FUNCTION "FC_GRP_81_R27" : VOID
TITLE =GROUP =81-R27
{ S7_language := '9(1) Angielski (Stany Zjednoczone)  11.01.2022  09:45:15' }
VERSION : 0.1


VAR_TEMP
  CL : "UDT_CABINET";	//CABINET LOCAL
  CR : "UDT_CABINET";	//CABINET REMOTE
  RelError : BOOL ;	//ERROR RELEASE
  RelErrorCL : BOOL ;	//ERROR RELEASE FROM CABINET LOCAL
  RelErrorCR : BOOL ;	//ERROR RELEASE FROM CABINET REMOTE
  RelControl : BOOL ;	//CONTROL RELEASE
  RelControlCL : BOOL ;	//CONTROL RELEASE FROM CABINET LOCAL
  RelControlCR : BOOL ;	//CONTROL RELEASE FROM CABINET REMOTE
  ErrorConfirm : BOOL ;	//ERROR CONFIRM
  AutoOn : BOOL ;	//AUTOMATIC ON
  AutoOff : BOOL ;	//AUTOMATIC OFF
  LAMP_ON : BOOL ;
  FLOW_METER_PE : BOOL ;
  ASU_FLAPS_MT34_STOP : BOOL ;
  ASU_FLAPS_MT34_CLOSE : BOOL ;
  ASU_PREHEATING_FINISHED : BOOL ;
  OUT_TEMP_SENSOR_OK : BOOL ;	//OUTSIDE TEMPERATURE SENSOR OK
  OUT_HUM_SENSOR_OK : BOOL ;	//OUTSIDE HUMIDITY SENSOR OK
  ASU_PUMP_COOLING_STOP : BOOL ;
  H_81CLM82_HUM_SWP : REAL ;
  T_81CLT81_HEAT_SWP : REAL ;
  T_81CLT81_HEAT_SWP_MAX : REAL ;
END_VAR
BEGIN
NETWORK
TITLE =GLOBAL SIGNALS

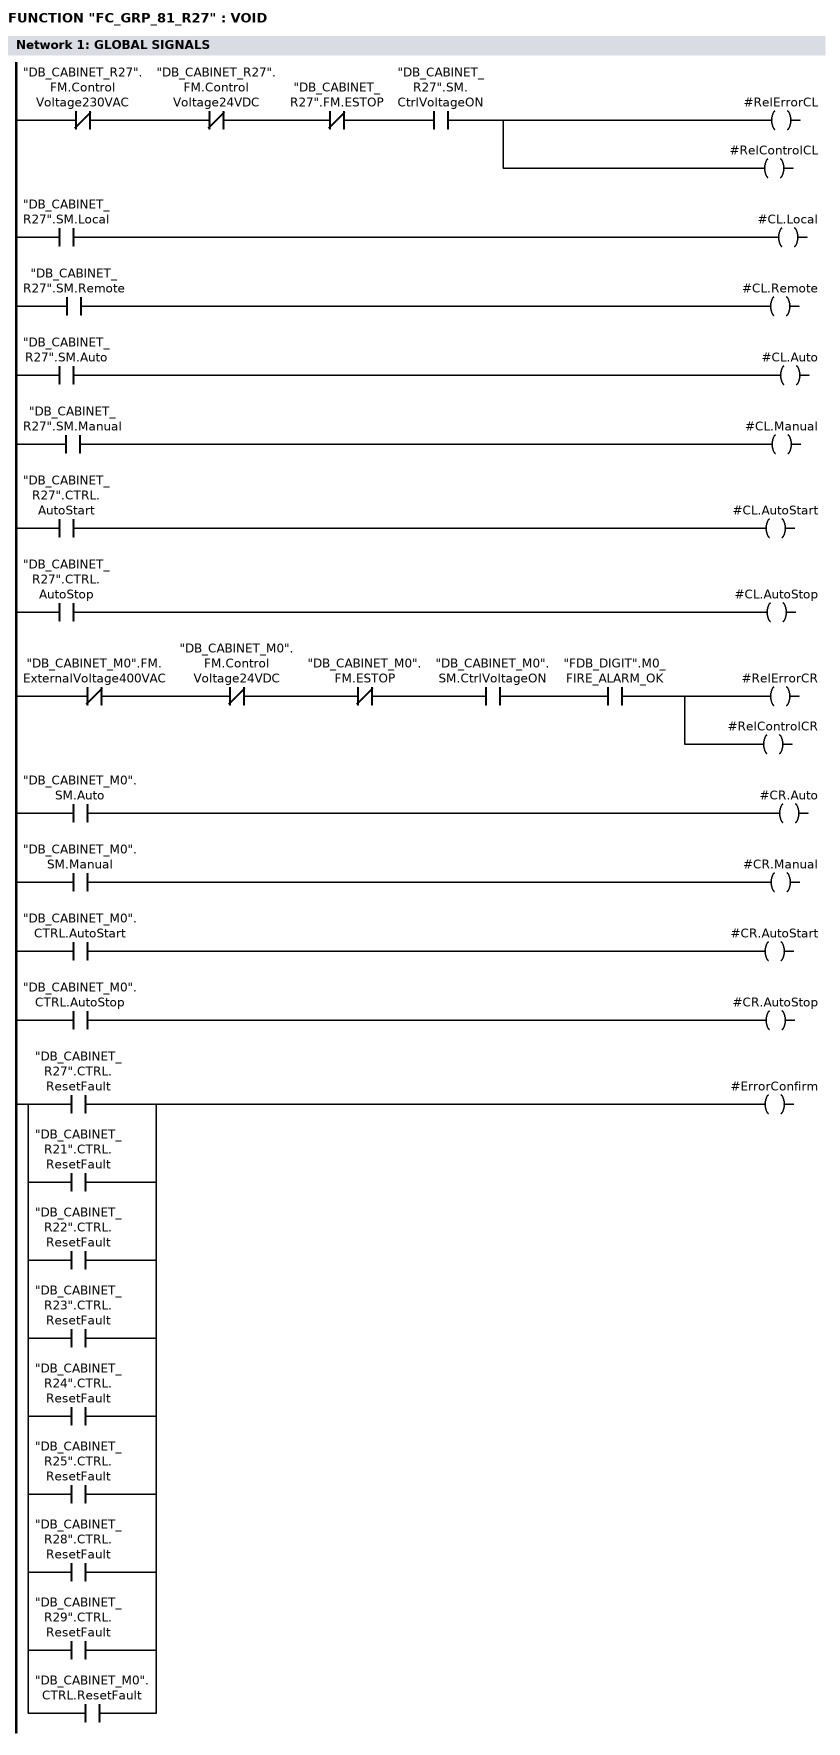
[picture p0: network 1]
// LOCAL
      UN    "DB_CABINET_R27".FM.ControlVoltage230VAC;
      UN    "DB_CABINET_R27".FM.ControlVoltage24VDC;
//      UN    "DB_CABINET_R27".FM.ControlVoltage230VAC_MS
      UN    "DB_CABINET_R27".FM.ESTOP;
      U     "DB_CABINET_R27".SM.CtrlVoltageON;
      =     #RelErrorCL;
      =     #RelControlCL;

      U     "DB_CABINET_R27".SM.Local;
      =     #CL.Local;
      U     "DB_CABINET_R27".SM.Remote;
      =     #CL.Remote;
      U     "DB_CABINET_R27".SM.Auto;
      =     #CL.Auto;
      U     "DB_CABINET_R27".SM.Manual;
      =     #CL.Manual;
      U     "DB_CABINET_R27".CTRL.AutoStart;
      =     #CL.AutoStart;
      U     "DB_CABINET_R27".CTRL.AutoStop;
      =     #CL.AutoStop;

// REMOTE
      UN    "DB_CABINET_M0".FM.ExternalVoltage400VAC;
      UN    "DB_CABINET_M0".FM.ControlVoltage24VDC;
//      UN    "DB_CABINET_M0".FM.ControlVoltage230VAC_MS
      UN    "DB_CABINET_M0".FM.ESTOP;
      U     "DB_CABINET_M0".SM.CtrlVoltageON;
      U     "FDB_DIGIT".M0_FIRE_ALARM_OK;
      =     #RelErrorCR;
      =     #RelControlCR;

      U     "DB_CABINET_M0".SM.Auto;
      =     #CR.Auto;
      U     "DB_CABINET_M0".SM.Manual;
      =     #CR.Manual;
      U     "DB_CABINET_M0".CTRL.AutoStart;
      =     #CR.AutoStart;
      U     "DB_CABINET_M0".CTRL.AutoStop;
      =     #CR.AutoStop;

      U     "DB_CABINET_R27".CTRL.ResetFault;
      O     "DB_CABINET_R21".CTRL.ResetFault;
      O     "DB_CABINET_R22".CTRL.ResetFault;
      O     "DB_CABINET_R23".CTRL.ResetFault;
      O     "DB_CABINET_R24".CTRL.ResetFault;
      O     "DB_CABINET_R25".CTRL.ResetFault;
      O     "DB_CABINET_R28".CTRL.ResetFault;
      O     "DB_CABINET_R29".CTRL.ResetFault;
      O     "DB_CABINET_M0".CTRL.ResetFault;
      =     #ErrorConfirm;

NETWORK
TITLE ==81DOO08-S1F ACCESS DOOR ERROR

      U(    ;
      U(    ;
      O     #ErrorConfirm;
      O     "R27-81DOO08+81TG1-S1:14";
      )     ;
      R     "DB_DIGIT".FM.G81_DOO08;
      U     "FDB_DIGIT".R27_81DOO08_OK;
      =     "DB_DIGIT".SM.G81_DOO08;
      U     "DB_DIGIT".SM.G81_DOO08;
      NOT   ;
      U     #RelErrorCL;
      U     #RelErrorCR;
      S     "DB_DIGIT".FM.G81_DOO08;
      U     "DB_DIGIT".FM.G81_DOO08;
      )     ;
      U     "DURATION_1";
      =     "R27-81DOO08+81TG1-H1:x1";
NETWORK
TITLE ==81FLA11/12/13/14 CONTROL/ERROR RELEASE

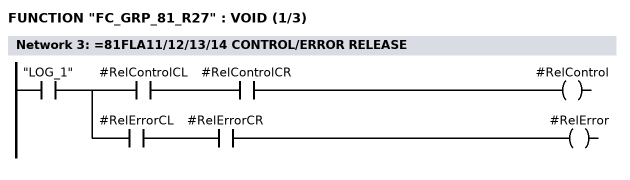
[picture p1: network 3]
      U     "LOG_1";
      =     L     20.0;
      U     L     20.0;
      U     #RelControlCL;
      U     #RelControlCR;
      =     #RelControl;
      U     L     20.0;
      U     #RelErrorCL;
      U     #RelErrorCR;
      =     #RelError;
NETWORK
TITLE ==81FLA11/12/13/14 CONTROL ALL FLAPS IN MAN. MODE / FIRE ALARM

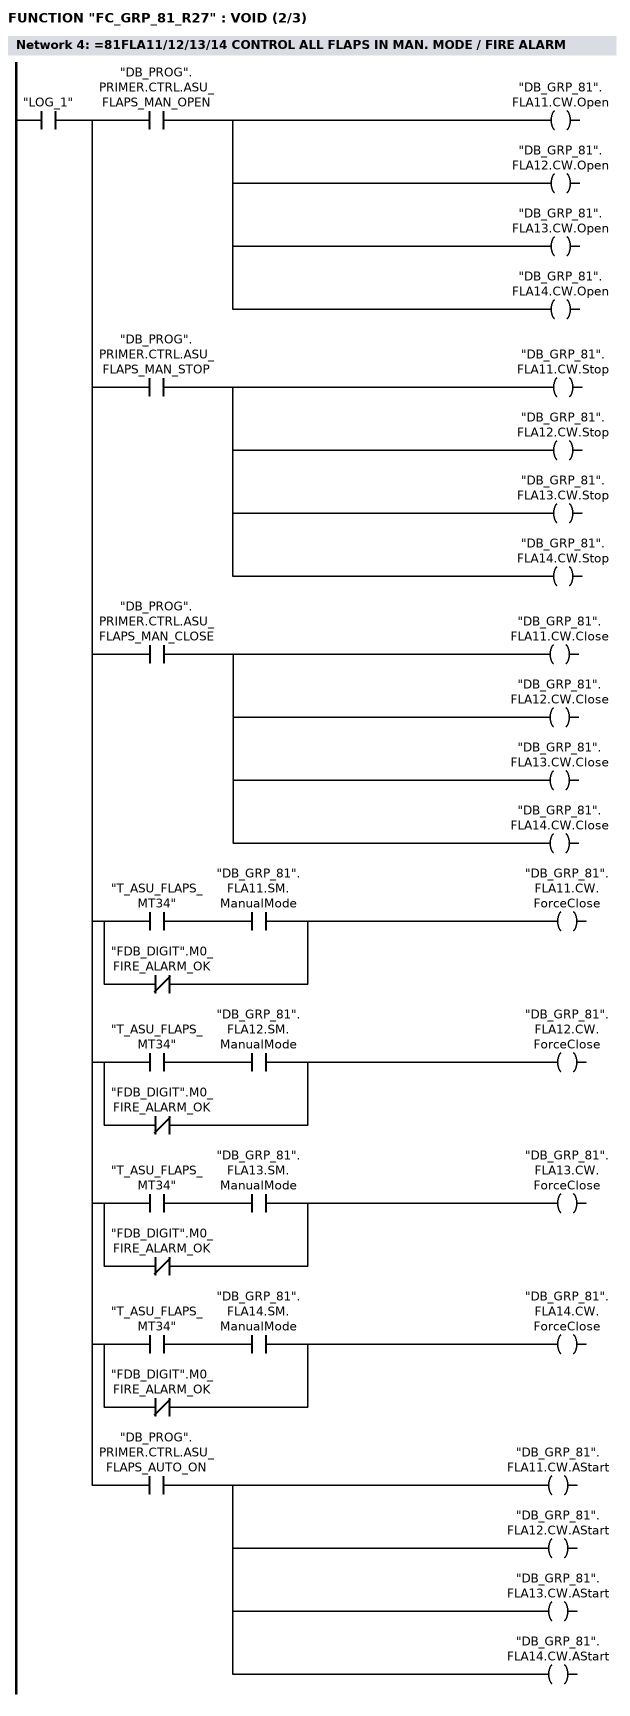
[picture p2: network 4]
      U     "LOG_1";
      =     L     20.0;
      U     L     20.0;
      U     "DB_PROG".PRIMER.CTRL.ASU_FLAPS_MAN_OPEN;
      =     "DB_GRP_81".FLA11.CW.Open;
      =     "DB_GRP_81".FLA12.CW.Open;
      =     "DB_GRP_81".FLA13.CW.Open;
      =     "DB_GRP_81".FLA14.CW.Open;
      U     L     20.0;
      U     "DB_PROG".PRIMER.CTRL.ASU_FLAPS_MAN_STOP;
      =     "DB_GRP_81".FLA11.CW.Stop;
      =     "DB_GRP_81".FLA12.CW.Stop;
      =     "DB_GRP_81".FLA13.CW.Stop;
      =     "DB_GRP_81".FLA14.CW.Stop;
      U     L     20.0;
      U     "DB_PROG".PRIMER.CTRL.ASU_FLAPS_MAN_CLOSE;
      =     "DB_GRP_81".FLA11.CW.Close;
      =     "DB_GRP_81".FLA12.CW.Close;
      =     "DB_GRP_81".FLA13.CW.Close;
      =     "DB_GRP_81".FLA14.CW.Close;
      U     L     20.0;
      U(    ;
      U     "T_ASU_FLAPS_MT34";
      U     "DB_GRP_81".FLA11.SM.ManualMode;
      ON    "FDB_DIGIT".M0_FIRE_ALARM_OK;
      )     ;
      =     "DB_GRP_81".FLA11.CW.ForceClose;
      U     L     20.0;
      U(    ;
      U     "T_ASU_FLAPS_MT34";
      U     "DB_GRP_81".FLA12.SM.ManualMode;
      ON    "FDB_DIGIT".M0_FIRE_ALARM_OK;
      )     ;
      =     "DB_GRP_81".FLA12.CW.ForceClose;
      U     L     20.0;
      U(    ;
      U     "T_ASU_FLAPS_MT34";
      U     "DB_GRP_81".FLA13.SM.ManualMode;
      ON    "FDB_DIGIT".M0_FIRE_ALARM_OK;
      )     ;
      =     "DB_GRP_81".FLA13.CW.ForceClose;
      U     L     20.0;
      U(    ;
      U     "T_ASU_FLAPS_MT34";
      U     "DB_GRP_81".FLA14.SM.ManualMode;
      ON    "FDB_DIGIT".M0_FIRE_ALARM_OK;
      )     ;
      =     "DB_GRP_81".FLA14.CW.ForceClose;
      U     L     20.0;
      U     "DB_PROG".PRIMER.CTRL.ASU_FLAPS_AUTO_ON;
      =     "DB_GRP_81".FLA11.CW.AStart;
      =     "DB_GRP_81".FLA12.CW.AStart;
      =     "DB_GRP_81".FLA13.CW.AStart;
      =     "DB_GRP_81".FLA14.CW.AStart;
NETWORK
TITLE ==81FLA11/12/13/14-M1 FROST PROTECTION TIMER

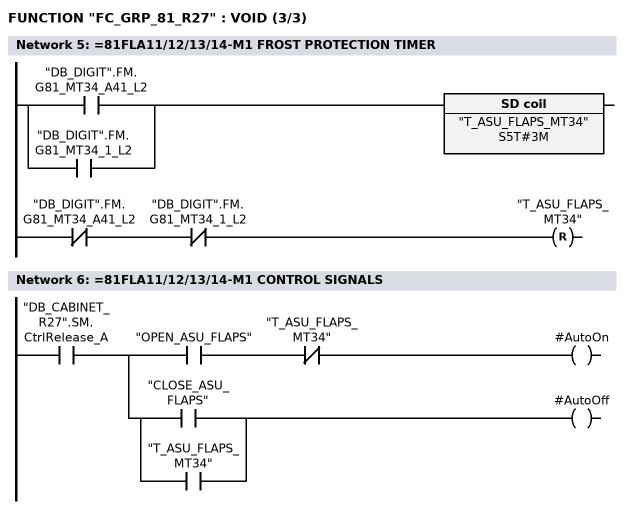
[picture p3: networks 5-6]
      U(    ;
      O     "DB_DIGIT".FM.G81_MT34_A41_L2;
      O     "DB_DIGIT".FM.G81_MT34_1_L2;
      )     ;
      L     S5T#3M;
      SE    "T_ASU_FLAPS_MT34";
      UN    "DB_DIGIT".FM.G81_MT34_A41_L2;
      UN    "DB_DIGIT".FM.G81_MT34_1_L2;
      R     "T_ASU_FLAPS_MT34";
      NOP   0;
      NOP   0;
      NOP   0;
NETWORK
TITLE ==81FLA11/12/13/14-M1 CONTROL SIGNALS

      U     "DB_CABINET_R27".SM.CtrlRelease_A;
      =     L     20.0;
      U     L     20.0;
      U     "OPEN_ASU_FLAPS";
      UN    "T_ASU_FLAPS_MT34";
      =     #AutoOn;
      U     L     20.0;
      U(    ;
      O     "CLOSE_ASU_FLAPS";
      O     "T_ASU_FLAPS_MT34";
      )     ;
      =     #AutoOff;
NETWORK
TITLE ==81FLA11-M1 CONTROL DAMPER

      U     #RelControl;
      =     L     20.0;
      BLD   103;
      U     #RelError;
      =     L     20.1;
      BLD   103;
      U     #AutoOn;
      =     L     20.2;
      BLD   103;
      U     #AutoOff;
      =     L     20.3;
      BLD   103;
      U     "LOG_1";
      =     L     20.4;
      BLD   103;
      U(    ;
      U     "R27-81FLA11+X-S1c:4";
      L     S5T#1M;
      SE    "T_81FLA11_LS_O";
      NOP   0;
      NOP   0;
      NOP   0;
      U     "T_81FLA11_LS_O";
      )     ;
      =     L     20.5;
      BLD   103;
      U(    ;
      U     "R27-81FLA11+X-S2c:4";
      L     S5T#1M;
      SE    "T_81FLA11_LS_C";
      NOP   0;
      NOP   0;
      NOP   0;
      U     "T_81FLA11_LS_C";
      )     ;
      =     L     20.6;
      BLD   103;
      U     #ErrorConfirm;
      =     L     20.7;
      BLD   103;
      CALL "FC_FLAP" (
           REL_CONTROL              := L     20.0,
           REL_ERROR                := L     20.1,
           CL                       := #CL,
           CR                       := #CR,
           AUTO_OPEN                := L     20.2,
           AUTO_CLOSE               := L     20.3,
           FUSE                     := L     20.4,
           LS_OPEN                  := L     20.5,
           LS_CLOSE                 := L     20.6,
           ERROR_CONFIRM            := L     20.7,
           MAX_RUNTIME              := 210,
           OPEN                     := "R27-81FLA11+X-M1:2",
           CLOSE                    := "R27-81FLA11+X-M1:3",
           DDB                      := "DB_GRP_81".FLA11);
      NOP   0;
NETWORK
TITLE ==81FLA12-M1 CONTROL DAMPER

      U     #RelControl;
      =     L     20.0;
      BLD   103;
      U     #RelError;
      =     L     20.1;
      BLD   103;
      U     #AutoOn;
      =     L     20.2;
      BLD   103;
      U     #AutoOff;
      =     L     20.3;
      BLD   103;
      U     "LOG_1";
      =     L     20.4;
      BLD   103;
      U(    ;
      U     "R27-81FLA12+X-S1c:4";
      L     S5T#1M;
      SE    "T_81FLA12_LS_O";
      NOP   0;
      NOP   0;
      NOP   0;
      U     "T_81FLA12_LS_O";
      )     ;
      =     L     20.5;
      BLD   103;
      U(    ;
      U     "R27-81FLA12+X-S2c:4";
      L     S5T#1M;
      SE    "T_81FLA12_LS_C";
      NOP   0;
      NOP   0;
      NOP   0;
      U     "T_81FLA12_LS_C";
      )     ;
      =     L     20.6;
      BLD   103;
      U     #ErrorConfirm;
      =     L     20.7;
      BLD   103;
      CALL "FC_FLAP" (
           REL_CONTROL              := L     20.0,
           REL_ERROR                := L     20.1,
           CL                       := #CL,
           CR                       := #CR,
           AUTO_OPEN                := L     20.2,
           AUTO_CLOSE               := L     20.3,
           FUSE                     := L     20.4,
           LS_OPEN                  := L     20.5,
           LS_CLOSE                 := L     20.6,
           ERROR_CONFIRM            := L     20.7,
           MAX_RUNTIME              := 210,
           OPEN                     := "R27-81FLA12+X-M1:2",
           CLOSE                    := "R27-81FLA12+X-M1:3",
           DDB                      := "DB_GRP_81".FLA12);
      NOP   0;
NETWORK
TITLE ==81FLA13-M1 CONTROL DAMPER

      U     #RelControl;
      =     L     20.0;
      BLD   103;
      U     #RelError;
      =     L     20.1;
      BLD   103;
      U     #AutoOn;
      =     L     20.2;
      BLD   103;
      U     #AutoOff;
      =     L     20.3;
      BLD   103;
      U     "LOG_1";
      =     L     20.4;
      BLD   103;
      U(    ;
      U     "R27-81FLA13+X-S1c:4";
      L     S5T#1M;
      SE    "T_81FLA13_LS_O";
      NOP   0;
      NOP   0;
      NOP   0;
      U     "T_81FLA13_LS_O";
      )     ;
      =     L     20.5;
      BLD   103;
      U(    ;
      U     "R27-81FLA13+X-S2c:4";
      L     S5T#1M;
      SE    "T_81FLA13_LS_C";
      NOP   0;
      NOP   0;
      NOP   0;
      U     "T_81FLA13_LS_C";
      )     ;
      =     L     20.6;
      BLD   103;
      U     #ErrorConfirm;
      =     L     20.7;
      BLD   103;
      CALL "FC_FLAP" (
           REL_CONTROL              := L     20.0,
           REL_ERROR                := L     20.1,
           CL                       := #CL,
           CR                       := #CR,
           AUTO_OPEN                := L     20.2,
           AUTO_CLOSE               := L     20.3,
           FUSE                     := L     20.4,
           LS_OPEN                  := L     20.5,
           LS_CLOSE                 := L     20.6,
           ERROR_CONFIRM            := L     20.7,
           MAX_RUNTIME              := 210,
           OPEN                     := "R27-81FLA13+X-M1:2",
           CLOSE                    := "R27-81FLA13+X-M1:3",
           DDB                      := "DB_GRP_81".FLA13);
      NOP   0;
NETWORK
TITLE ==81FLA14-M1 CONTROL DAMPER

      U     #RelControl;
      =     L     20.0;
      BLD   103;
      U     #RelError;
      =     L     20.1;
      BLD   103;
      U     #AutoOn;
      =     L     20.2;
      BLD   103;
      U     #AutoOff;
      =     L     20.3;
      BLD   103;
      U     "LOG_1";
      =     L     20.4;
      BLD   103;
      U(    ;
      U     "R27-81FLA14+X-S1c:4";
      L     S5T#1M;
      SE    "T_81FLA14_LS_O";
      NOP   0;
      NOP   0;
      NOP   0;
      U     "T_81FLA14_LS_O";
      )     ;
      =     L     20.5;
      BLD   103;
      U(    ;
      U     "R27-81FLA14+X-S2c:4";
      L     S5T#1M;
      SE    "T_81FLA14_LS_C";
      NOP   0;
      NOP   0;
      NOP   0;
      U     "T_81FLA14_LS_C";
      )     ;
      =     L     20.6;
      BLD   103;
      U     #ErrorConfirm;
      =     L     20.7;
      BLD   103;
      CALL "FC_FLAP" (
           REL_CONTROL              := L     20.0,
           REL_ERROR                := L     20.1,
           CL                       := #CL,
           CR                       := #CR,
           AUTO_OPEN                := L     20.2,
           AUTO_CLOSE               := L     20.3,
           FUSE                     := L     20.4,
           LS_OPEN                  := L     20.5,
           LS_CLOSE                 := L     20.6,
           ERROR_CONFIRM            := L     20.7,
           MAX_RUNTIME              := 210,
           OPEN                     := "R27-81FLA14+X-M1:2",
           CLOSE                    := "R27-81FLA14+X-M1:3",
           DDB                      := "DB_GRP_81".FLA14);
      NOP   0;
NETWORK
TITLE ==81FTR20-B33 FILTER PRESSURE MONITORING

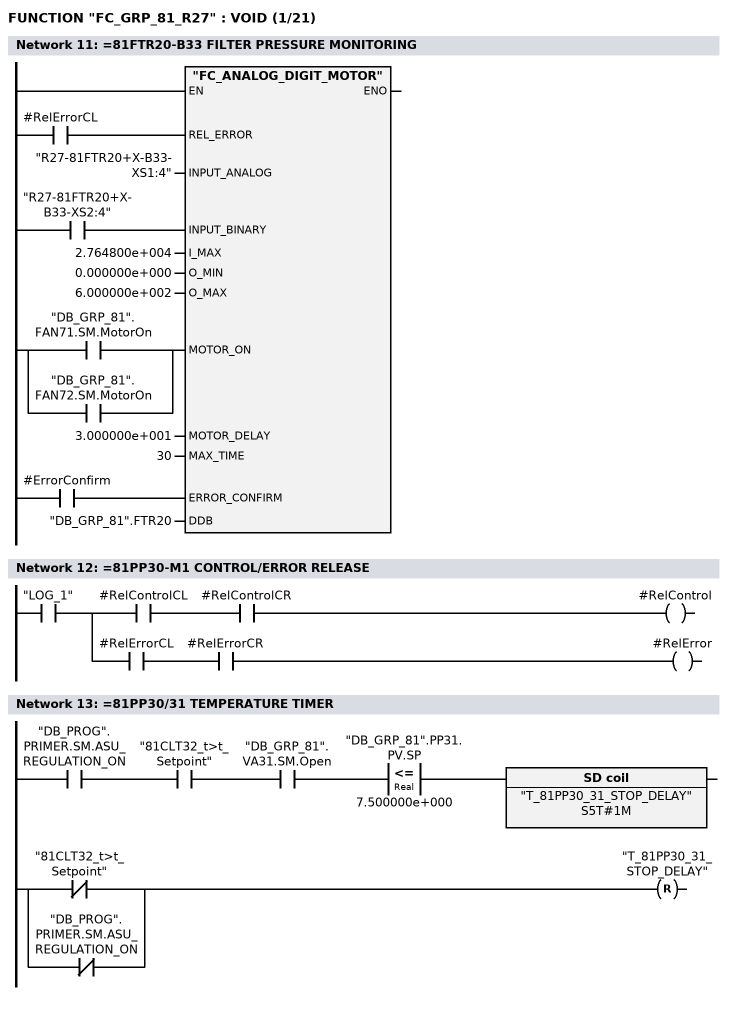
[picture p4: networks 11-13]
      U     #RelErrorCL;
      =     L     20.0;
      BLD   103;
      U     "R27-81FTR20+X-B33-XS2:4";
      =     L     20.1;
      BLD   103;
      U(    ;
      O     "DB_GRP_81".FAN71.SM.MotorOn;
      O     "DB_GRP_81".FAN72.SM.MotorOn;
      )     ;
      =     L     20.2;
      BLD   103;
      U     #ErrorConfirm;
      =     L     20.3;
      BLD   103;
      CALL "FC_ANALOG_DIGIT_MOTOR" (
           REL_ERROR                := L     20.0,
           INPUT_ANALOG             := "R27-81FTR20+X-B33-XS1:4",
           INPUT_BINARY             := L     20.1,
           I_MAX                    := 2.764800e+004,
           O_MIN                    := 0.000000e+000,
           O_MAX                    := 6.000000e+002,
           MOTOR_ON                 := L     20.2,
           MOTOR_DELAY              := 3.000000e+001,
           MAX_TIME                 := 30,
           ERROR_CONFIRM            := L     20.3,
           DDB                      := "DB_GRP_81".FTR20);
      NOP   0;
NETWORK
TITLE ==81PP30-M1 CONTROL/ERROR RELEASE

      U     "LOG_1";
      =     L     20.0;
      U     L     20.0;
      U     #RelControlCL;
      U     #RelControlCR;
      =     #RelControl;
      U     L     20.0;
      U     #RelErrorCL;
      U     #RelErrorCR;
      =     #RelError;
NETWORK
TITLE ==81PP30/31 TEMPERATURE TIMER

      U     "DB_PROG".PRIMER.SM.ASU_REGULATION_ON;
      U     "81CLT32_t>t_Setpoint";
      U     "DB_GRP_81".VA31.SM.Open;
      U(    ;
      L     "DB_GRP_81".PP31.PV.SP;
      L     7.500000e+000;
      <=R   ;
      )     ;
      L     S5T#1M;
      SE    "T_81PP30_31_STOP_DELAY";
      U(    ;
      ON    "81CLT32_t>t_Setpoint";
      ON    "DB_PROG".PRIMER.SM.ASU_REGULATION_ON;
      )     ;
      R     "T_81PP30_31_STOP_DELAY";
      NOP   0;
      NOP   0;
      NOP   0;
NETWORK
TITLE ==81PP30/31 FROST PROTECTION TIMER

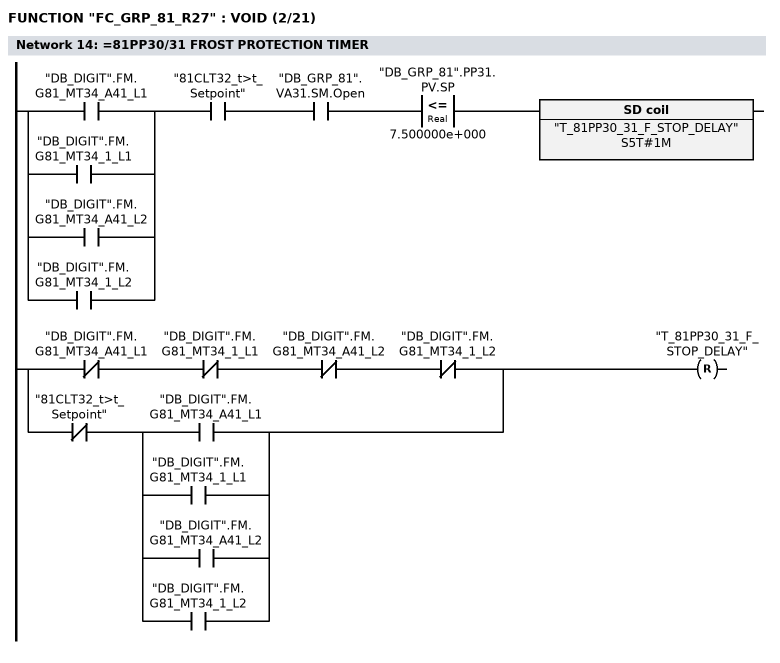
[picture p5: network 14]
      U(    ;
      O     "DB_DIGIT".FM.G81_MT34_A41_L1;
      O     "DB_DIGIT".FM.G81_MT34_1_L1;
      O     "DB_DIGIT".FM.G81_MT34_A41_L2;
      O     "DB_DIGIT".FM.G81_MT34_1_L2;
      )     ;
      U     "81CLT32_t>t_Setpoint";
      U     "DB_GRP_81".VA31.SM.Open;
      U(    ;
      L     "DB_GRP_81".PP31.PV.SP;
      L     7.500000e+000;
      <=R   ;
      )     ;
      L     S5T#1M;
      SE    "T_81PP30_31_F_STOP_DELAY";
      U(    ;
      UN    "DB_DIGIT".FM.G81_MT34_A41_L1;
      UN    "DB_DIGIT".FM.G81_MT34_1_L1;
      UN    "DB_DIGIT".FM.G81_MT34_A41_L2;
      UN    "DB_DIGIT".FM.G81_MT34_1_L2;
      O     ;
      UN    "81CLT32_t>t_Setpoint";
      U(    ;
      O     "DB_DIGIT".FM.G81_MT34_A41_L1;
      O     "DB_DIGIT".FM.G81_MT34_1_L1;
      O     "DB_DIGIT".FM.G81_MT34_A41_L2;
      O     "DB_DIGIT".FM.G81_MT34_1_L2;
      )     ;
      )     ;
      R     "T_81PP30_31_F_STOP_DELAY";
      NOP   0;
      NOP   0;
      NOP   0;
NETWORK
TITLE ==81PP30-M1 CONTROL SIGNALS

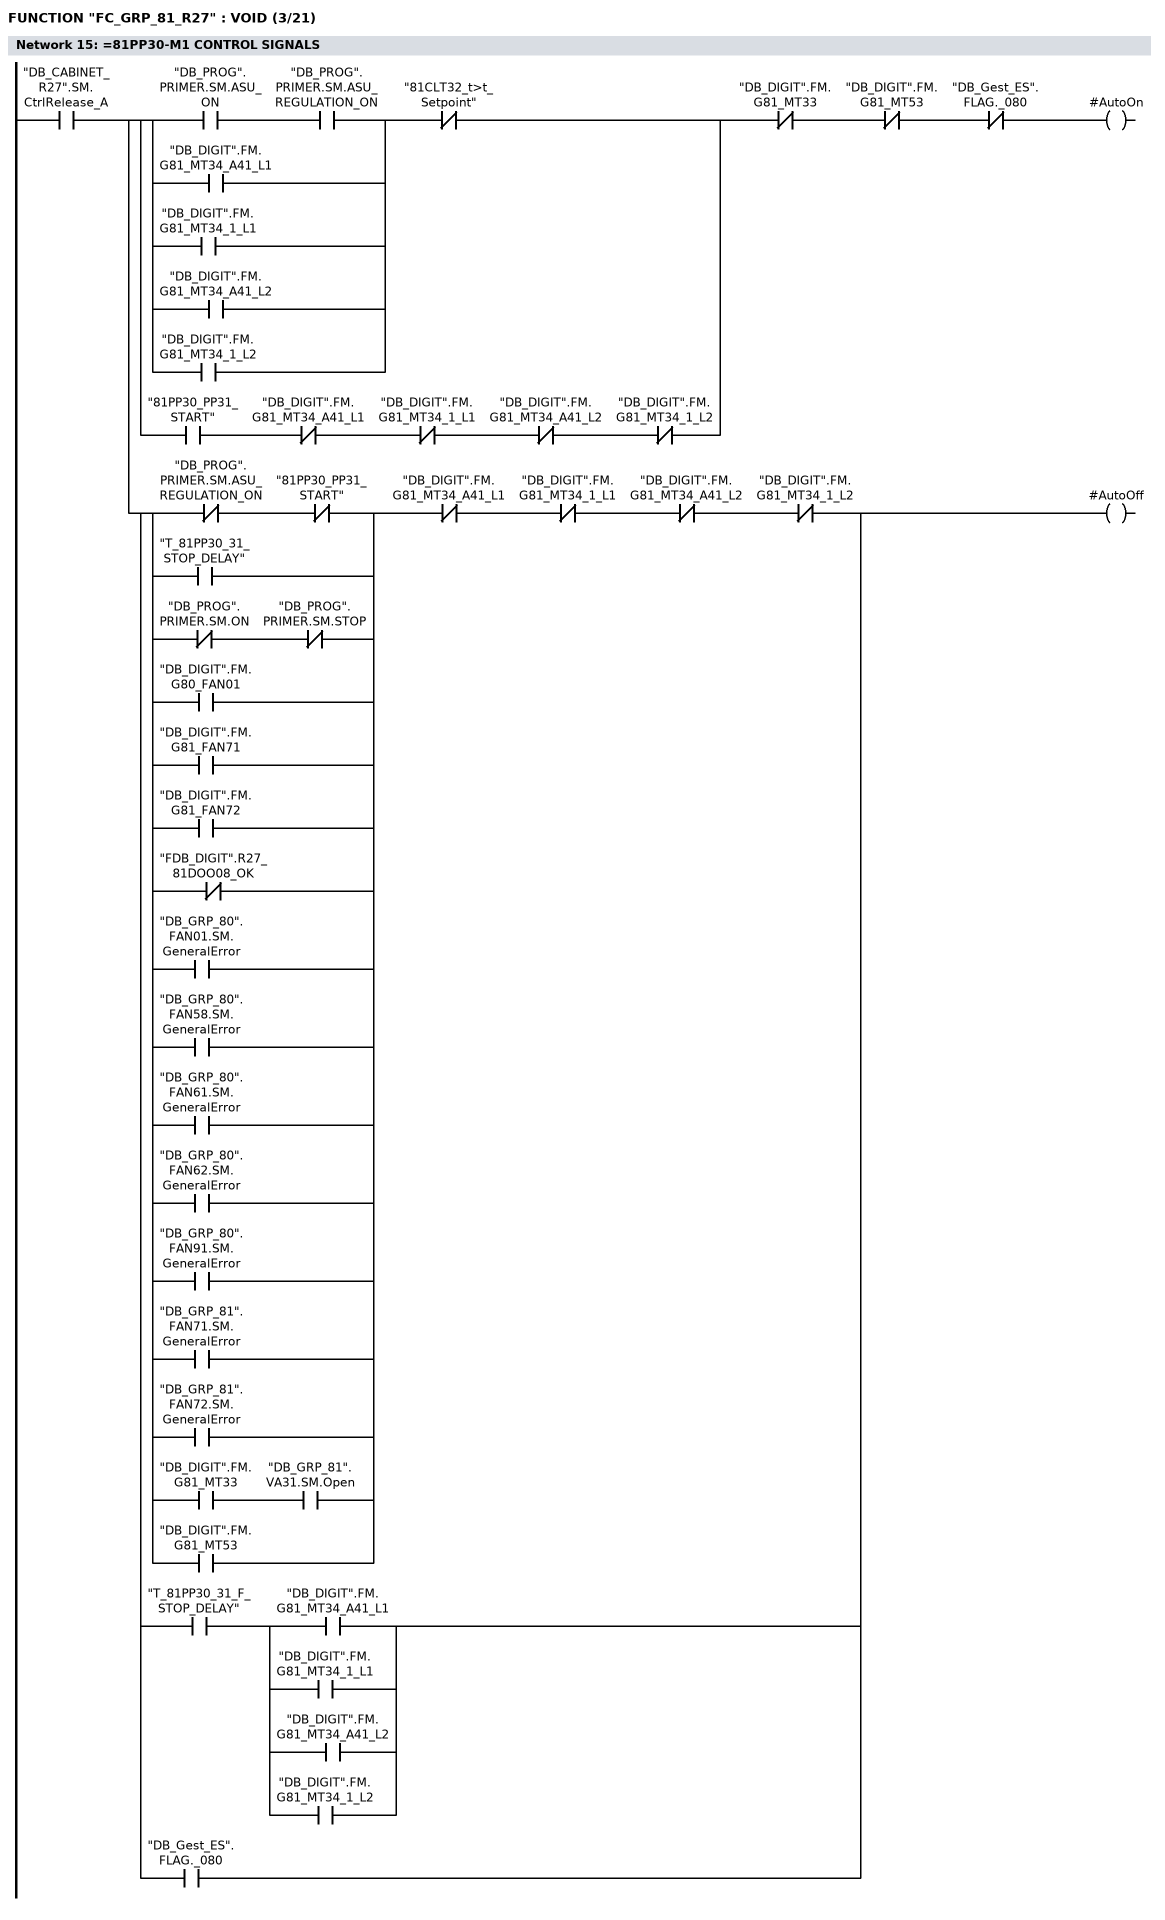
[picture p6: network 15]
      U     "DB_CABINET_R27".SM.CtrlRelease_A;
      =     L     20.0;
      U     L     20.0;
      U(    ;
      U(    ;
      U     "DB_PROG".PRIMER.SM.ASU_ON;
      U     "DB_PROG".PRIMER.SM.ASU_REGULATION_ON;
      O     "DB_DIGIT".FM.G81_MT34_A41_L1;
      O     "DB_DIGIT".FM.G81_MT34_1_L1;
      O     "DB_DIGIT".FM.G81_MT34_A41_L2;
      O     "DB_DIGIT".FM.G81_MT34_1_L2;
      )     ;
      UN    "81CLT32_t>t_Setpoint";
      O     ;
      U     "81PP30_PP31_START";
      UN    "DB_DIGIT".FM.G81_MT34_A41_L1;
      UN    "DB_DIGIT".FM.G81_MT34_1_L1;
      UN    "DB_DIGIT".FM.G81_MT34_A41_L2;
      UN    "DB_DIGIT".FM.G81_MT34_1_L2;
      )     ;
      UN    "DB_DIGIT".FM.G81_MT33;
      UN    "DB_DIGIT".FM.G81_MT53;
      UN    "DB_Gest_ES".FLAG._080;
      =     #AutoOn;
      U     L     20.0;
      U(    ;
      U(    ;
      UN    "DB_PROG".PRIMER.SM.ASU_REGULATION_ON;
      UN    "81PP30_PP31_START";
      O     "T_81PP30_31_STOP_DELAY";
      O     ;
      UN    "DB_PROG".PRIMER.SM.ON;
      UN    "DB_PROG".PRIMER.SM.STOP;
      O     "DB_DIGIT".FM.G80_FAN01;
      O     "DB_DIGIT".FM.G81_FAN71;
      O     "DB_DIGIT".FM.G81_FAN72;
      ON    "FDB_DIGIT".R27_81DOO08_OK;
      O     "DB_GRP_80".FAN01.SM.GeneralError;
      O     "DB_GRP_80".FAN58.SM.GeneralError;
      O     "DB_GRP_80".FAN61.SM.GeneralError;
      O     "DB_GRP_80".FAN62.SM.GeneralError;
      O     "DB_GRP_80".FAN91.SM.GeneralError;
      O     "DB_GRP_81".FAN71.SM.GeneralError;
      O     "DB_GRP_81".FAN72.SM.GeneralError;
      O     ;
      U     "DB_DIGIT".FM.G81_MT33;
      U     "DB_GRP_81".VA31.SM.Open;
      O     "DB_DIGIT".FM.G81_MT53;
      )     ;
      UN    "DB_DIGIT".FM.G81_MT34_A41_L1;
      UN    "DB_DIGIT".FM.G81_MT34_1_L1;
      UN    "DB_DIGIT".FM.G81_MT34_A41_L2;
      UN    "DB_DIGIT".FM.G81_MT34_1_L2;
      O     ;
      U     "T_81PP30_31_F_STOP_DELAY";
      U(    ;
      O     "DB_DIGIT".FM.G81_MT34_A41_L1;
      O     "DB_DIGIT".FM.G81_MT34_1_L1;
      O     "DB_DIGIT".FM.G81_MT34_A41_L2;
      O     "DB_DIGIT".FM.G81_MT34_1_L2;
      )     ;
      O     "DB_Gest_ES".FLAG._080;
      )     ;
      =     #AutoOff;
NETWORK
TITLE ==81PP30-M1 PREHEATING PUMP

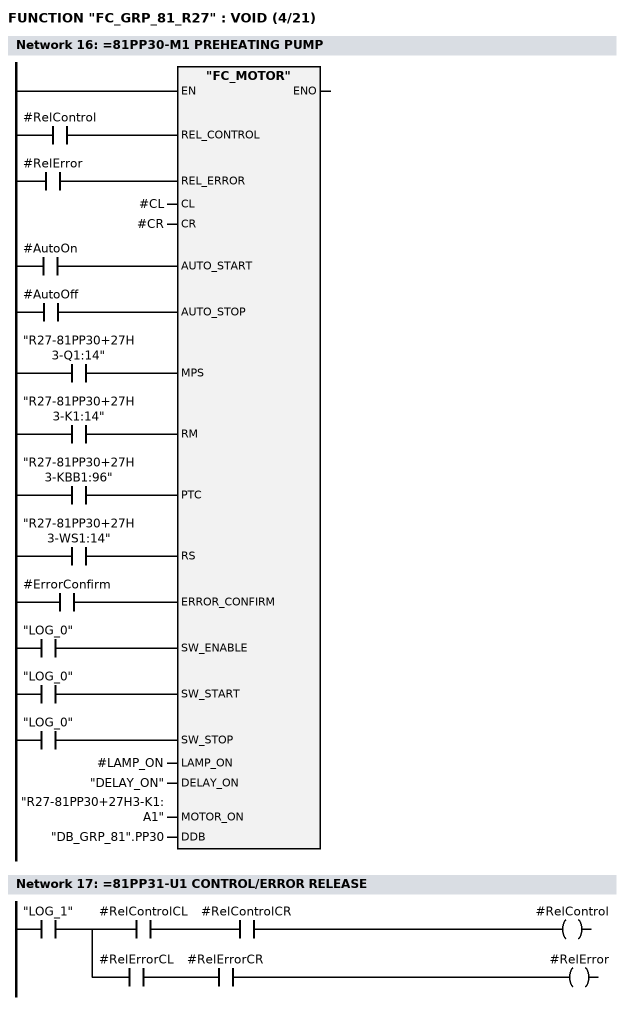
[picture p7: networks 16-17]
      U     #RelControl;
      =     L     20.0;
      BLD   103;
      U     #RelError;
      =     L     20.1;
      BLD   103;
      U     #AutoOn;
      =     L     20.2;
      BLD   103;
      U     #AutoOff;
      =     L     20.3;
      BLD   103;
      U     "R27-81PP30+27H3-Q1:14";
      =     L     20.4;
      BLD   103;
      U     "R27-81PP30+27H3-K1:14";
      =     L     20.5;
      BLD   103;
      U     "R27-81PP30+27H3-KBB1:96";
      =     L     20.6;
      BLD   103;
      U     "R27-81PP30+27H3-WS1:14";
      =     L     20.7;
      BLD   103;
      U     #ErrorConfirm;
      =     L     21.0;
      BLD   103;
      U     "LOG_0";
      =     L     21.1;
      BLD   103;
      U     "LOG_0";
      =     L     21.2;
      BLD   103;
      U     "LOG_0";
      =     L     21.3;
      BLD   103;
      CALL "FC_MOTOR" (
           REL_CONTROL              := L     20.0,
           REL_ERROR                := L     20.1,
           CL                       := #CL,
           CR                       := #CR,
           AUTO_START               := L     20.2,
           AUTO_STOP                := L     20.3,
           MPS                      := L     20.4,
           RM                       := L     20.5,
           PTC                      := L     20.6,
           RS                       := L     20.7,
           ERROR_CONFIRM            := L     21.0,
           SW_ENABLE                := L     21.1,
           SW_START                 := L     21.2,
           SW_STOP                  := L     21.3,
           LAMP_ON                  := #LAMP_ON,
           DELAY_ON                 := "DELAY_ON",
           MOTOR_ON                 := "R27-81PP30+27H3-K1:A1",
           DDB                      := "DB_GRP_81".PP30);
      NOP   0;
NETWORK
TITLE ==81PP31-U1 CONTROL/ERROR RELEASE

      U     "LOG_1";
      =     L     20.0;
      U     L     20.0;
      U     #RelControlCL;
      U     #RelControlCR;
      =     #RelControl;
      U     L     20.0;
      U     #RelErrorCL;
      U     #RelErrorCR;
      =     #RelError;
NETWORK
TITLE ==81PP31-U1 CONTROL SIGNALS

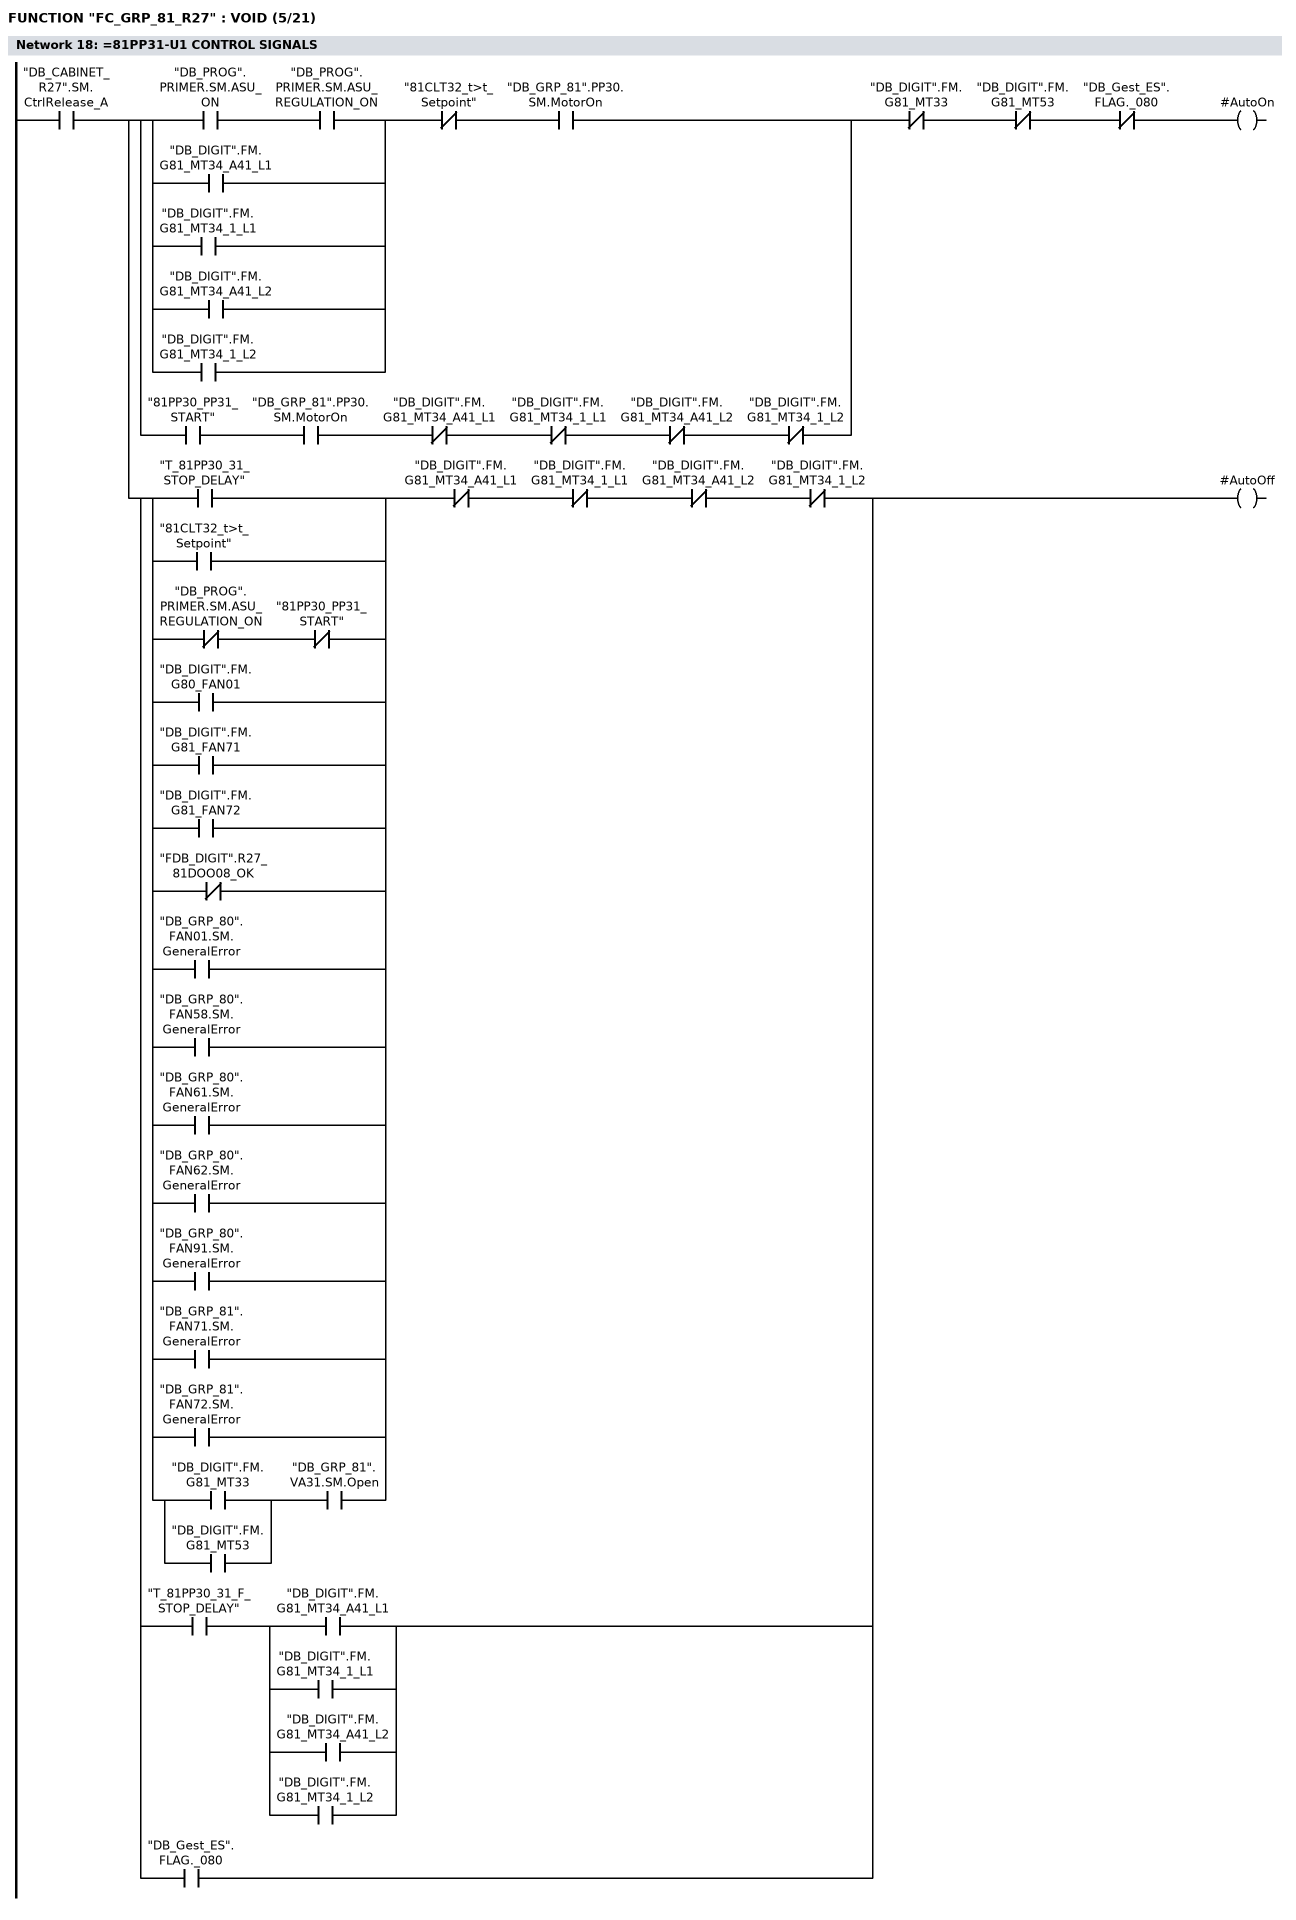
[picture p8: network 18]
      U     "DB_CABINET_R27".SM.CtrlRelease_A;
      =     L     20.0;
      U     L     20.0;
      U(    ;
      U(    ;
      U     "DB_PROG".PRIMER.SM.ASU_ON;
      U     "DB_PROG".PRIMER.SM.ASU_REGULATION_ON;
      O     "DB_DIGIT".FM.G81_MT34_A41_L1;
      O     "DB_DIGIT".FM.G81_MT34_1_L1;
      O     "DB_DIGIT".FM.G81_MT34_A41_L2;
      O     "DB_DIGIT".FM.G81_MT34_1_L2;
      )     ;
      UN    "81CLT32_t>t_Setpoint";
      U     "DB_GRP_81".PP30.SM.MotorOn;
      O     ;
      U     "81PP30_PP31_START";
      U     "DB_GRP_81".PP30.SM.MotorOn;
      UN    "DB_DIGIT".FM.G81_MT34_A41_L1;
      UN    "DB_DIGIT".FM.G81_MT34_1_L1;
      UN    "DB_DIGIT".FM.G81_MT34_A41_L2;
      UN    "DB_DIGIT".FM.G81_MT34_1_L2;
      )     ;
      UN    "DB_DIGIT".FM.G81_MT33;
      UN    "DB_DIGIT".FM.G81_MT53;
      UN    "DB_Gest_ES".FLAG._080;
      =     #AutoOn;
      U     L     20.0;
      U(    ;
      U(    ;
      O     "T_81PP30_31_STOP_DELAY";
      O     "81CLT32_t>t_Setpoint";
      O     ;
      UN    "DB_PROG".PRIMER.SM.ASU_REGULATION_ON;
      UN    "81PP30_PP31_START";
      O     "DB_DIGIT".FM.G80_FAN01;
      O     "DB_DIGIT".FM.G81_FAN71;
      O     "DB_DIGIT".FM.G81_FAN72;
      ON    "FDB_DIGIT".R27_81DOO08_OK;
      O     "DB_GRP_80".FAN01.SM.GeneralError;
      O     "DB_GRP_80".FAN58.SM.GeneralError;
      O     "DB_GRP_80".FAN61.SM.GeneralError;
      O     "DB_GRP_80".FAN62.SM.GeneralError;
      O     "DB_GRP_80".FAN91.SM.GeneralError;
      O     "DB_GRP_81".FAN71.SM.GeneralError;
      O     "DB_GRP_81".FAN72.SM.GeneralError;
      O     ;
      U(    ;
      O     "DB_DIGIT".FM.G81_MT33;
      O     "DB_DIGIT".FM.G81_MT53;
      )     ;
      U     "DB_GRP_81".VA31.SM.Open;
      )     ;
      UN    "DB_DIGIT".FM.G81_MT34_A41_L1;
      UN    "DB_DIGIT".FM.G81_MT34_1_L1;
      UN    "DB_DIGIT".FM.G81_MT34_A41_L2;
      UN    "DB_DIGIT".FM.G81_MT34_1_L2;
      O     ;
      U     "T_81PP30_31_F_STOP_DELAY";
      U(    ;
      O     "DB_DIGIT".FM.G81_MT34_A41_L1;
      O     "DB_DIGIT".FM.G81_MT34_1_L1;
      O     "DB_DIGIT".FM.G81_MT34_A41_L2;
      O     "DB_DIGIT".FM.G81_MT34_1_L2;
      )     ;
      O     "DB_Gest_ES".FLAG._080;
      )     ;
      =     #AutoOff;
NETWORK
TITLE ==81PP31-U1 PREHEATING PUMP SETPOINT TRANSFER

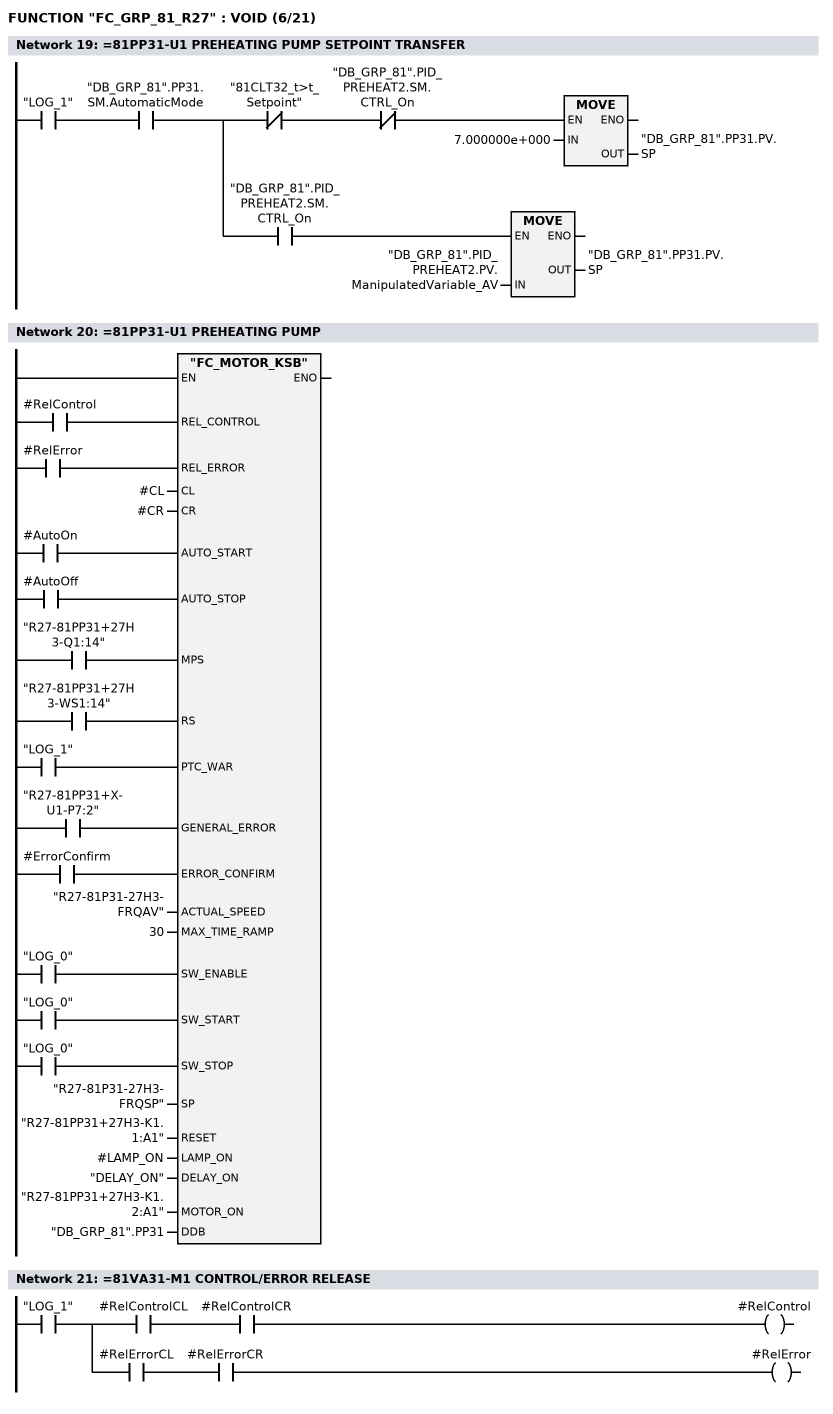
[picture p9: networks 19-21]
      U     "LOG_1";
      U     "DB_GRP_81".PP31.SM.AutomaticMode;
      =     L     20.0;
      U     L     20.0;
      UN    "81CLT32_t>t_Setpoint";
      UN    "DB_GRP_81".PID_PREHEAT2.SM.CTRL_On;
      SPBNB _001;
      L     7.000000e+000;
      T     "DB_GRP_81".PP31.PV.SP;
_001: NOP   0;
      U     L     20.0;
      U     "DB_GRP_81".PID_PREHEAT2.SM.CTRL_On;
      SPBNB _002;
      L     "DB_GRP_81".PID_PREHEAT2.PV.ManipulatedVariable_AV;
      T     "DB_GRP_81".PP31.PV.SP;
_002: NOP   0;
NETWORK
TITLE ==81PP31-U1 PREHEATING PUMP

      U     #RelControl;
      =     L     20.0;
      BLD   103;
      U     #RelError;
      =     L     20.1;
      BLD   103;
      U     #AutoOn;
      =     L     20.2;
      BLD   103;
      U     #AutoOff;
      =     L     20.3;
      BLD   103;
      U     "R27-81PP31+27H3-Q1:14";
      =     L     20.4;
      BLD   103;
      U     "R27-81PP31+27H3-WS1:14";
      =     L     20.5;
      BLD   103;
      U     "LOG_1";
      =     L     20.6;
      BLD   103;
      U     "R27-81PP31+X-U1-P7:2";
      =     L     20.7;
      BLD   103;
      U     #ErrorConfirm;
      =     L     21.0;
      BLD   103;
      U     "LOG_0";
      =     L     21.1;
      BLD   103;
      U     "LOG_0";
      =     L     21.2;
      BLD   103;
      U     "LOG_0";
      =     L     21.3;
      BLD   103;
      CALL "FC_MOTOR_KSB" (
           REL_CONTROL              := L     20.0,
           REL_ERROR                := L     20.1,
           CL                       := #CL,
           CR                       := #CR,
           AUTO_START               := L     20.2,
           AUTO_STOP                := L     20.3,
           MPS                      := L     20.4,
           RS                       := L     20.5,
           PTC_WAR                  := L     20.6,
           GENERAL_ERROR            := L     20.7,
           ERROR_CONFIRM            := L     21.0,
           ACTUAL_SPEED             := "R27-81P31-27H3-FRQAV",
           MAX_TIME_RAMP            := 30,
           SW_ENABLE                := L     21.1,
           SW_START                 := L     21.2,
           SW_STOP                  := L     21.3,
           SP                       := "R27-81P31-27H3-FRQSP",
           RESET                    := "R27-81PP31+27H3-K1.1:A1",
           LAMP_ON                  := #LAMP_ON,
           DELAY_ON                 := "DELAY_ON",
           MOTOR_ON                 := "R27-81PP31+27H3-K1.2:A1",
           DDB                      := "DB_GRP_81".PP31);
      NOP   0;
NETWORK
TITLE ==81VA31-M1 CONTROL/ERROR RELEASE

      U     "LOG_1";
      =     L     20.0;
      U     L     20.0;
      U     #RelControlCL;
      U     #RelControlCR;
      =     #RelControl;
      U     L     20.0;
      U     #RelErrorCL;
      U     #RelErrorCR;
      =     #RelError;
NETWORK
TITLE ==81VA31-M1 CONTROL VALVE HEATING CONTROL SIGNALS

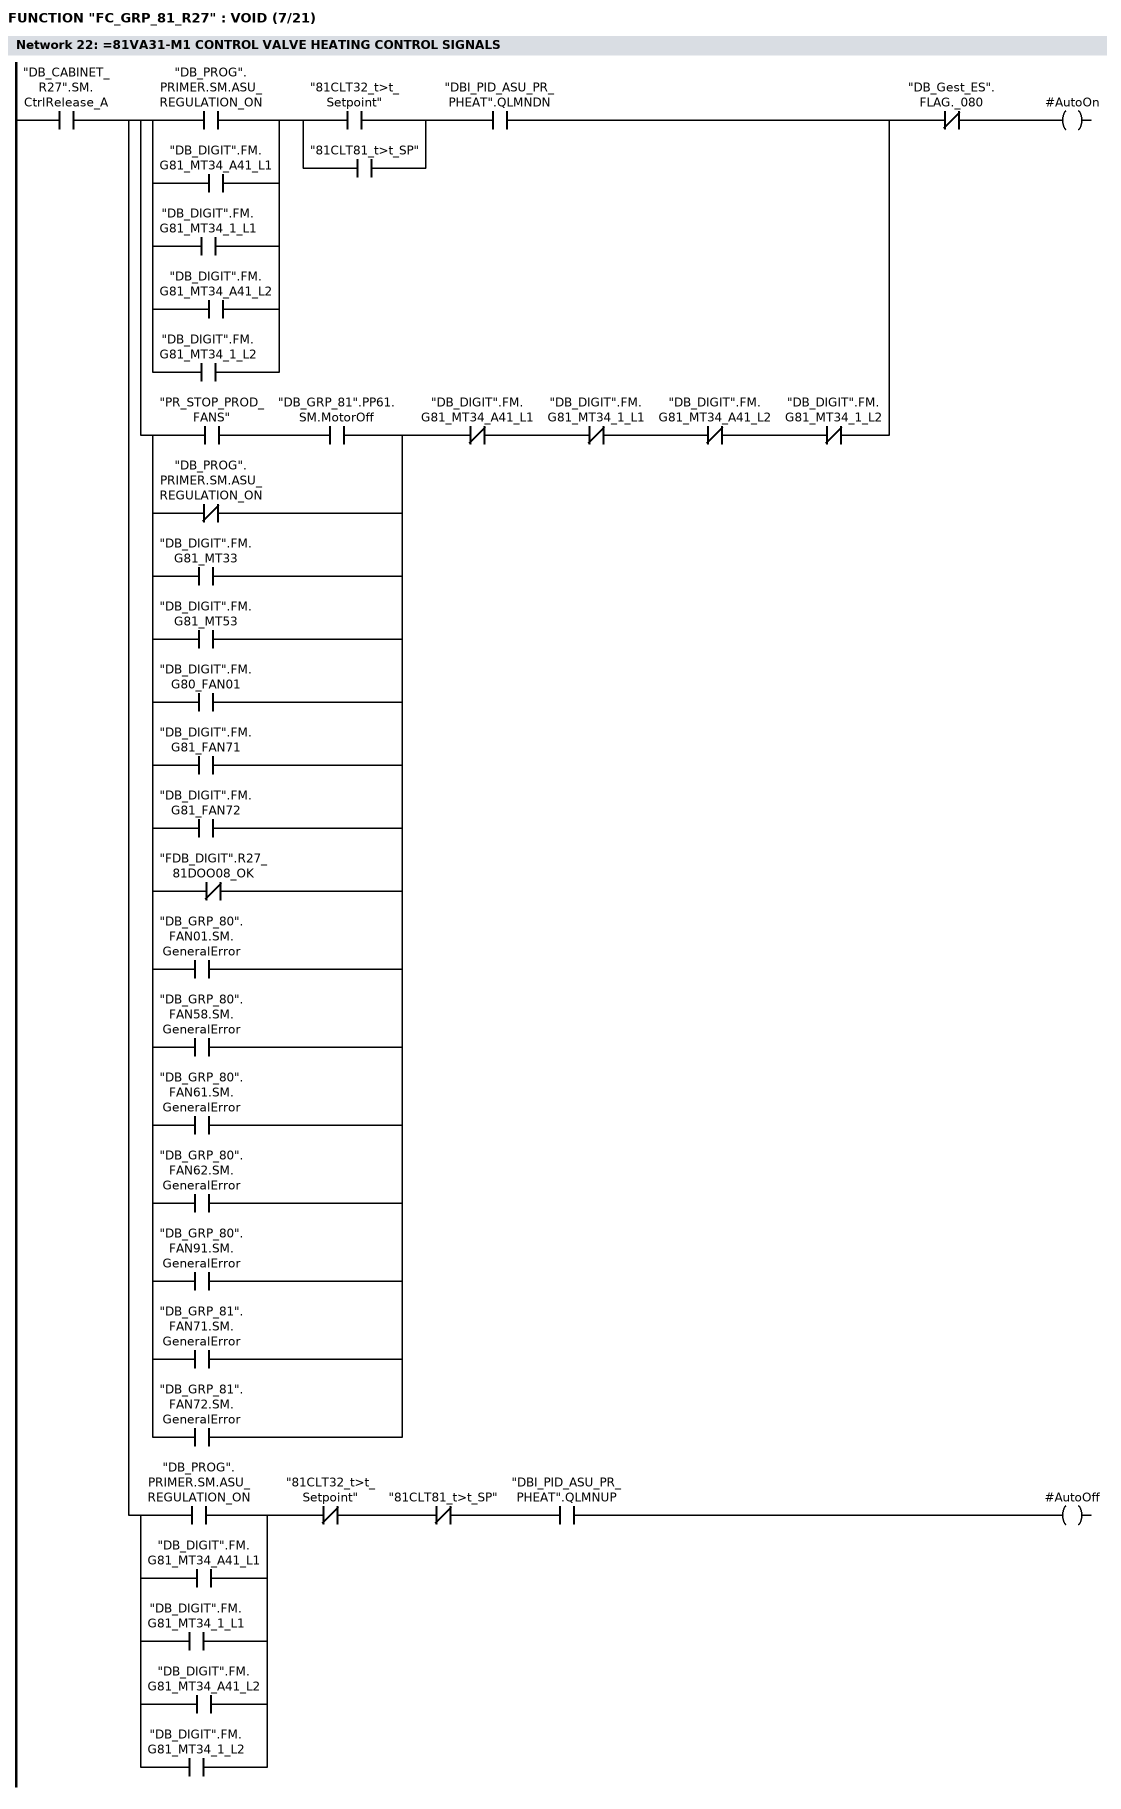
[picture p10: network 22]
      U     "DB_CABINET_R27".SM.CtrlRelease_A;
      =     L     20.0;
      U     L     20.0;
      U(    ;
      U(    ;
      O     "DB_PROG".PRIMER.SM.ASU_REGULATION_ON;
      O     "DB_DIGIT".FM.G81_MT34_A41_L1;
      O     "DB_DIGIT".FM.G81_MT34_1_L1;
      O     "DB_DIGIT".FM.G81_MT34_A41_L2;
      O     "DB_DIGIT".FM.G81_MT34_1_L2;
      )     ;
      U(    ;
      O     "81CLT32_t>t_Setpoint";
      O     "81CLT81_t>t_SP";
      )     ;
      U     "DBI_PID_ASU_PR_PHEAT".QLMNDN;
      O     ;
      U(    ;
      U     "PR_STOP_PROD_FANS";
      U     "DB_GRP_81".PP61.SM.MotorOff;
      ON    "DB_PROG".PRIMER.SM.ASU_REGULATION_ON;
      O     "DB_DIGIT".FM.G81_MT33;
      O     "DB_DIGIT".FM.G81_MT53;
      O     "DB_DIGIT".FM.G80_FAN01;
      O     "DB_DIGIT".FM.G81_FAN71;
      O     "DB_DIGIT".FM.G81_FAN72;
      ON    "FDB_DIGIT".R27_81DOO08_OK;
      O     "DB_GRP_80".FAN01.SM.GeneralError;
      O     "DB_GRP_80".FAN58.SM.GeneralError;
      O     "DB_GRP_80".FAN61.SM.GeneralError;
      O     "DB_GRP_80".FAN62.SM.GeneralError;
      O     "DB_GRP_80".FAN91.SM.GeneralError;
      O     "DB_GRP_81".FAN71.SM.GeneralError;
      O     "DB_GRP_81".FAN72.SM.GeneralError;
      )     ;
      UN    "DB_DIGIT".FM.G81_MT34_A41_L1;
      UN    "DB_DIGIT".FM.G81_MT34_1_L1;
      UN    "DB_DIGIT".FM.G81_MT34_A41_L2;
      UN    "DB_DIGIT".FM.G81_MT34_1_L2;
      )     ;
      UN    "DB_Gest_ES".FLAG._080;
      =     #AutoOn;
      U     L     20.0;
      U(    ;
      O     "DB_PROG".PRIMER.SM.ASU_REGULATION_ON;
      O     "DB_DIGIT".FM.G81_MT34_A41_L1;
      O     "DB_DIGIT".FM.G81_MT34_1_L1;
      O     "DB_DIGIT".FM.G81_MT34_A41_L2;
      O     "DB_DIGIT".FM.G81_MT34_1_L2;
      )     ;
      UN    "81CLT32_t>t_Setpoint";
      UN    "81CLT81_t>t_SP";
      U     "DBI_PID_ASU_PR_PHEAT".QLMNUP;
      =     #AutoOff;
NETWORK
TITLE =FIRE ALARM CLOSE

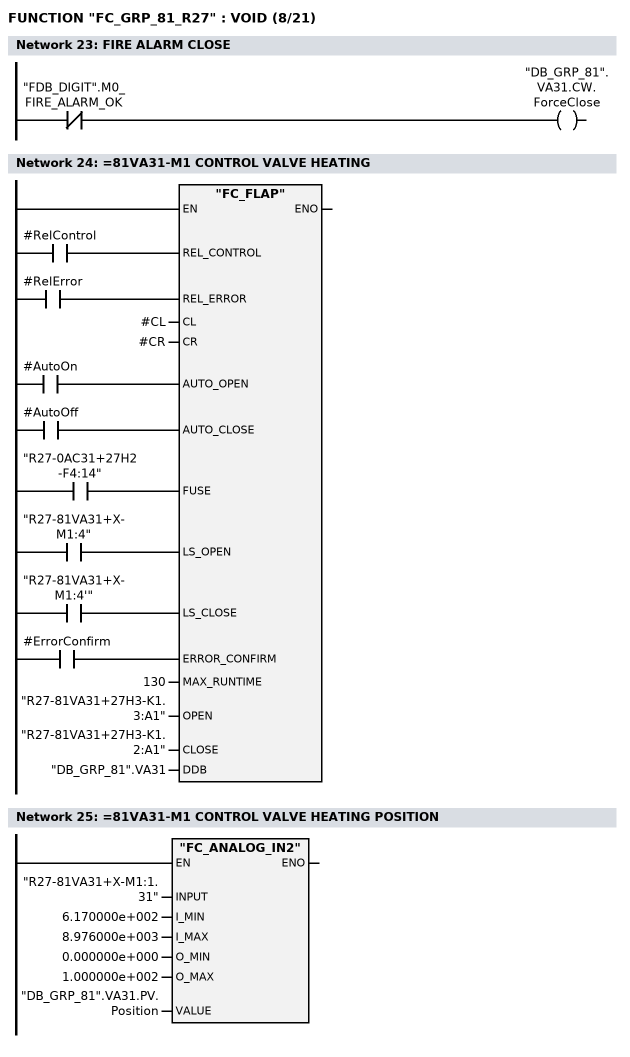
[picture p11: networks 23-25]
      UN    "FDB_DIGIT".M0_FIRE_ALARM_OK;
      =     "DB_GRP_81".VA31.CW.ForceClose;
NETWORK
TITLE ==81VA31-M1 CONTROL VALVE HEATING

      U     #RelControl;
      =     L     20.0;
      BLD   103;
      U     #RelError;
      =     L     20.1;
      BLD   103;
      U     #AutoOn;
      =     L     20.2;
      BLD   103;
      U     #AutoOff;
      =     L     20.3;
      BLD   103;
      U     "R27-0AC31+27H2-F4:14";
      =     L     20.4;
      BLD   103;
      U     "R27-81VA31+X-M1:4";
      =     L     20.5;
      BLD   103;
      U     "R27-81VA31+X-M1:4'";
      =     L     20.6;
      BLD   103;
      U     #ErrorConfirm;
      =     L     20.7;
      BLD   103;
      CALL "FC_FLAP" (
           REL_CONTROL              := L     20.0,
           REL_ERROR                := L     20.1,
           CL                       := #CL,
           CR                       := #CR,
           AUTO_OPEN                := L     20.2,
           AUTO_CLOSE               := L     20.3,
           FUSE                     := L     20.4,
           LS_OPEN                  := L     20.5,
           LS_CLOSE                 := L     20.6,
           ERROR_CONFIRM            := L     20.7,
           MAX_RUNTIME              := 130,
           OPEN                     := "R27-81VA31+27H3-K1.3:A1",
           CLOSE                    := "R27-81VA31+27H3-K1.2:A1",
           DDB                      := "DB_GRP_81".VA31);
      NOP   0;
NETWORK
TITLE ==81VA31-M1 CONTROL VALVE HEATING POSITION

      CALL "FC_ANALOG_IN2" (
           INPUT                    := "R27-81VA31+X-M1:1.31",
           I_MIN                    := 6.170000e+002,
           I_MAX                    := 8.976000e+003,
           O_MIN                    := 0.000000e+000,
           O_MAX                    := 1.000000e+002,
           VALUE                    := "DB_GRP_81".VA31.PV.Position);
      NOP   0;
NETWORK
TITLE =FORCE 81CLT32-B40N ERR. REL. IF WINDOW IS NOT REACHED AFTER TIME

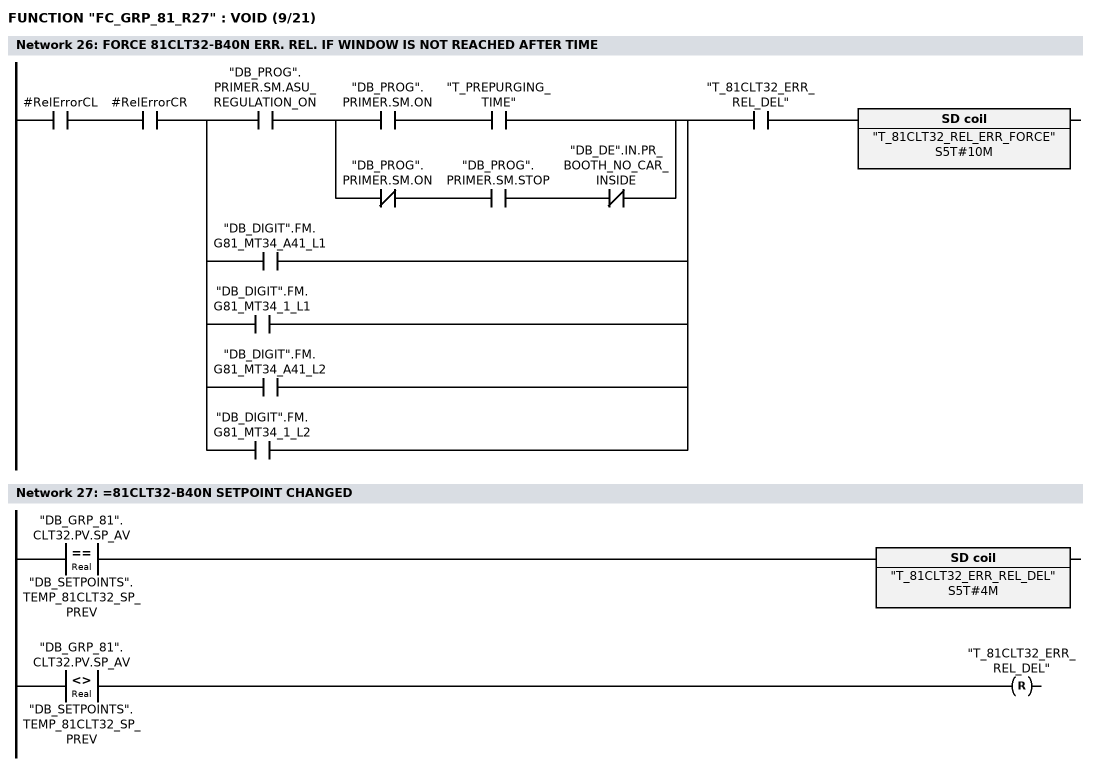
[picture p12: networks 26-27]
      U     #RelErrorCL;
      U     #RelErrorCR;
      U(    ;
      U     "DB_PROG".PRIMER.SM.ASU_REGULATION_ON;
      U(    ;
      U     "DB_PROG".PRIMER.SM.ON;
      U     "T_PREPURGING_TIME";
      O     ;
      UN    "DB_PROG".PRIMER.SM.ON;
      U     "DB_PROG".PRIMER.SM.STOP;
      UN    "DB_DE".IN.PR_BOOTH_NO_CAR_INSIDE;
      )     ;
      O     "DB_DIGIT".FM.G81_MT34_A41_L1;
      O     "DB_DIGIT".FM.G81_MT34_1_L1;
      O     "DB_DIGIT".FM.G81_MT34_A41_L2;
      O     "DB_DIGIT".FM.G81_MT34_1_L2;
      )     ;
      U     "T_81CLT32_ERR_REL_DEL";
      L     S5T#10M;
      SE    "T_81CLT32_REL_ERR_FORCE";
      NOP   0;
      NOP   0;
      NOP   0;
      NOP   0;
NETWORK
TITLE ==81CLT32-B40N SETPOINT CHANGED

      U(    ;
      L     "DB_GRP_81".CLT32.PV.SP_AV;
      L     "DB_SETPOINTS".TEMP_81CLT32_SP_PREV;
      ==R   ;
      )     ;
      L     S5T#4M;
      SE    "T_81CLT32_ERR_REL_DEL";
      U(    ;
      L     "DB_GRP_81".CLT32.PV.SP_AV;
      L     "DB_SETPOINTS".TEMP_81CLT32_SP_PREV;
      <>R   ;
      )     ;
      R     "T_81CLT32_ERR_REL_DEL";
      NOP   0;
      NOP   0;
      NOP   0;
NETWORK
TITLE ==81CLT32-B40N TEMPERATURE MONITORING

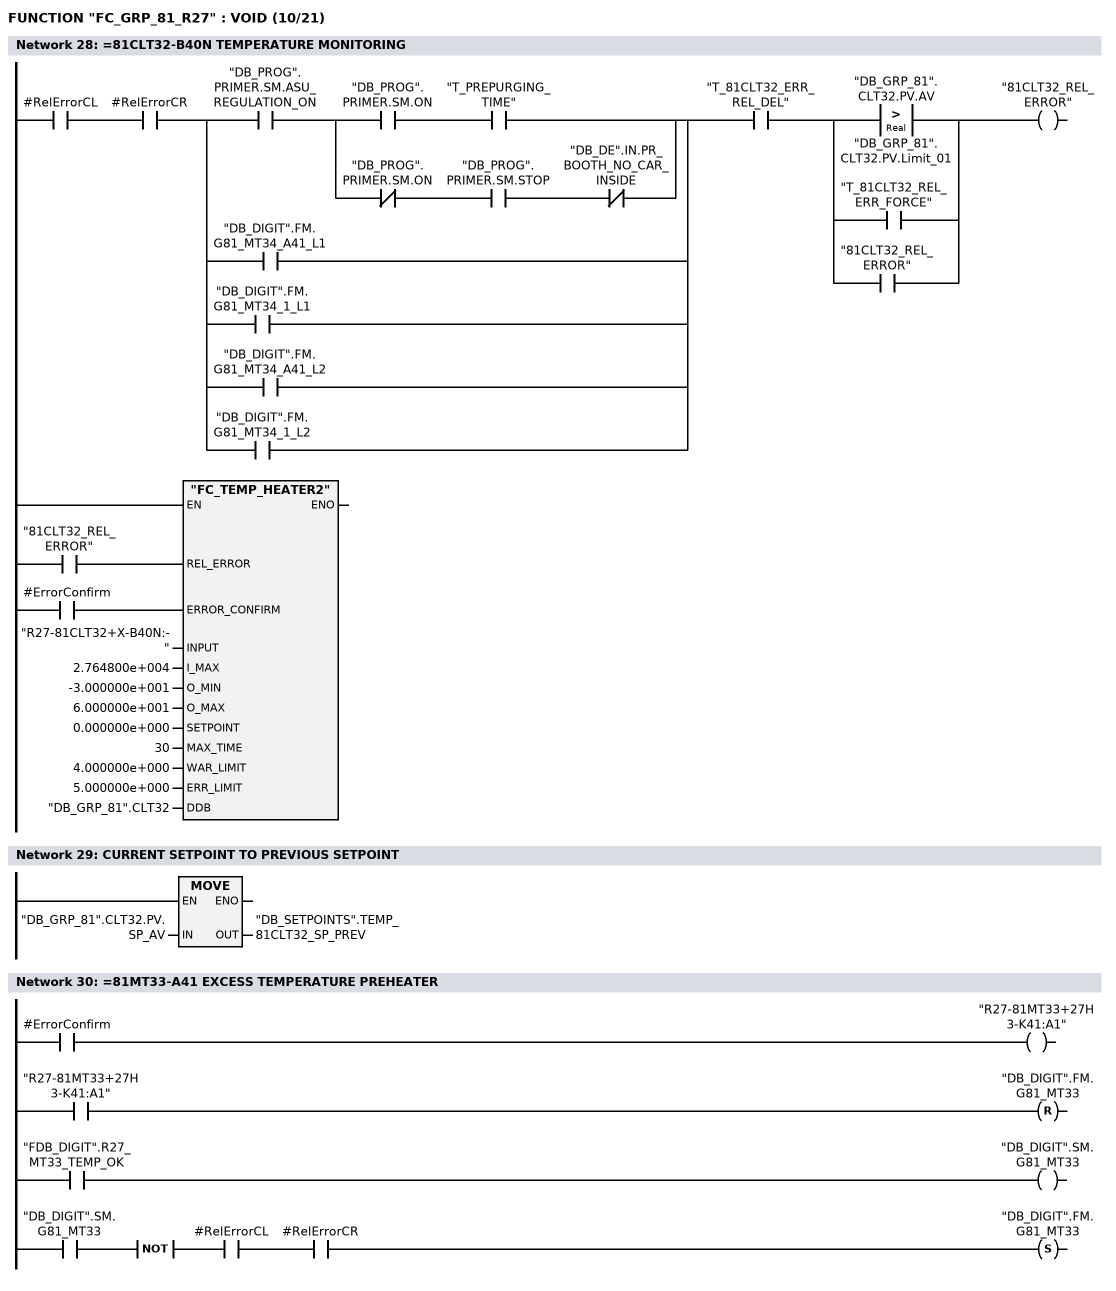
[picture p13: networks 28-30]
      U     #RelErrorCL;
      U     #RelErrorCR;
      U(    ;
      U     "DB_PROG".PRIMER.SM.ASU_REGULATION_ON;
      U(    ;
      U     "DB_PROG".PRIMER.SM.ON;
      U     "T_PREPURGING_TIME";
      O     ;
      UN    "DB_PROG".PRIMER.SM.ON;
      U     "DB_PROG".PRIMER.SM.STOP;
      UN    "DB_DE".IN.PR_BOOTH_NO_CAR_INSIDE;
      )     ;
      O     "DB_DIGIT".FM.G81_MT34_A41_L1;
      O     "DB_DIGIT".FM.G81_MT34_1_L1;
      O     "DB_DIGIT".FM.G81_MT34_A41_L2;
      O     "DB_DIGIT".FM.G81_MT34_1_L2;
      )     ;
      U     "T_81CLT32_ERR_REL_DEL";
      U(    ;
      O(    ;
      L     "DB_GRP_81".CLT32.PV.AV;
      L     "DB_GRP_81".CLT32.PV.Limit_01;
      >R    ;
      )     ;
      O     "T_81CLT32_REL_ERR_FORCE";
      O     "81CLT32_REL_ERROR";
      )     ;
      =     "81CLT32_REL_ERROR";
      U     "81CLT32_REL_ERROR";
      =     L     20.0;
      BLD   103;
      U     #ErrorConfirm;
      =     L     20.1;
      BLD   103;
      CALL "FC_TEMP_HEATER2" (
           REL_ERROR                := L     20.0,
           ERROR_CONFIRM            := L     20.1,
           INPUT                    := "R27-81CLT32+X-B40N:-",
           I_MAX                    := 2.764800e+004,
           O_MIN                    := -3.000000e+001,
           O_MAX                    := 6.000000e+001,
           SETPOINT                 := 0.000000e+000,
           MAX_TIME                 := 30,
           WAR_LIMIT                := 4.000000e+000,
           ERR_LIMIT                := 5.000000e+000,
           DDB                      := "DB_GRP_81".CLT32);
      NOP   0;
NETWORK
TITLE =CURRENT SETPOINT TO PREVIOUS SETPOINT

      L     "DB_GRP_81".CLT32.PV.SP_AV;
      T     "DB_SETPOINTS".TEMP_81CLT32_SP_PREV;
      NOP   0;
NETWORK
TITLE ==81MT33-A41 EXCESS TEMPERATURE PREHEATER

      U     #ErrorConfirm;
      =     "R27-81MT33+27H3-K41:A1";
      U     "R27-81MT33+27H3-K41:A1";
      R     "DB_DIGIT".FM.G81_MT33;
      U     "FDB_DIGIT".R27_MT33_TEMP_OK;
      =     "DB_DIGIT".SM.G81_MT33;
      U     "DB_DIGIT".SM.G81_MT33;
      NOT   ;
      U     #RelErrorCL;
      U     #RelErrorCR;
      S     "DB_DIGIT".FM.G81_MT33;
      NOP   0;
NETWORK
TITLE ==81MT34-B84 FROST PROTECTION WARNING

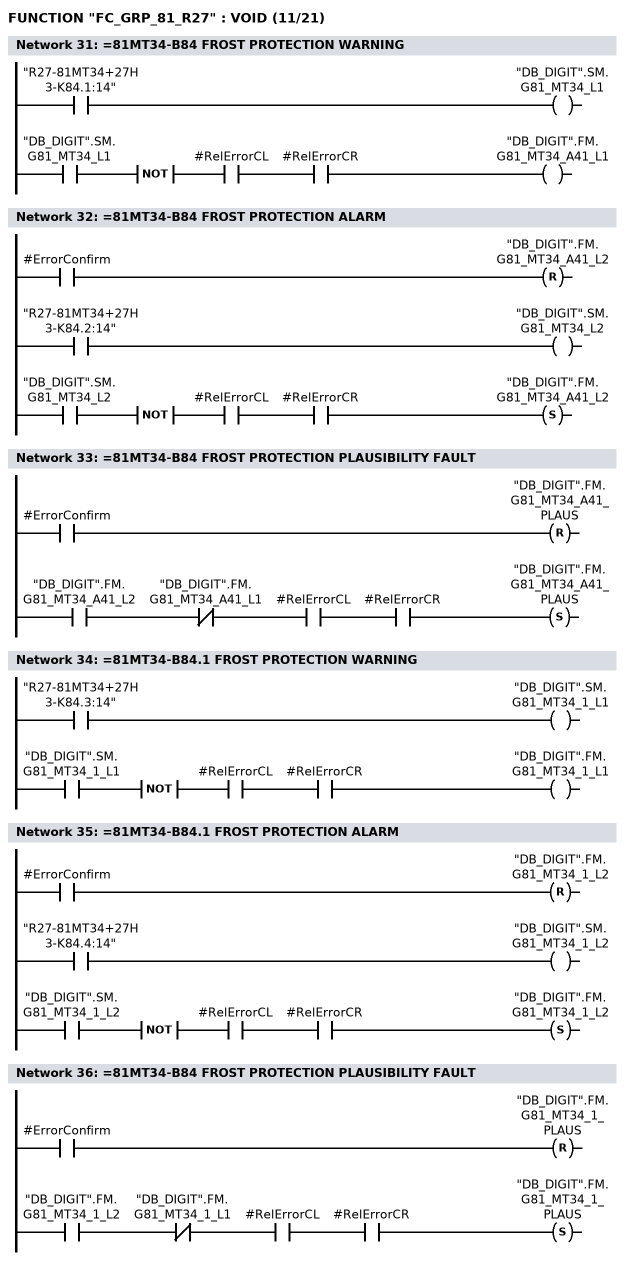
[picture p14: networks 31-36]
      U     "R27-81MT34+27H3-K84.1:14";
      =     "DB_DIGIT".SM.G81_MT34_L1;
      U     "DB_DIGIT".SM.G81_MT34_L1;
      NOT   ;
      U     #RelErrorCL;
      U     #RelErrorCR;
      =     "DB_DIGIT".FM.G81_MT34_A41_L1;
NETWORK
TITLE ==81MT34-B84 FROST PROTECTION ALARM

      U     #ErrorConfirm;
      R     "DB_DIGIT".FM.G81_MT34_A41_L2;
      U     "R27-81MT34+27H3-K84.2:14";
      =     "DB_DIGIT".SM.G81_MT34_L2;
      U     "DB_DIGIT".SM.G81_MT34_L2;
      NOT   ;
      U     #RelErrorCL;
      U     #RelErrorCR;
      S     "DB_DIGIT".FM.G81_MT34_A41_L2;
      NOP   0;
NETWORK
TITLE ==81MT34-B84 FROST PROTECTION PLAUSIBILITY FAULT

      U     #ErrorConfirm;
      R     "DB_DIGIT".FM.G81_MT34_A41_PLAUS;
      U     "DB_DIGIT".FM.G81_MT34_A41_L2;
      UN    "DB_DIGIT".FM.G81_MT34_A41_L1;
      U     #RelErrorCL;
      U     #RelErrorCR;
      S     "DB_DIGIT".FM.G81_MT34_A41_PLAUS;
      NOP   0;
NETWORK
TITLE ==81MT34-B84.1 FROST PROTECTION WARNING

      U     "R27-81MT34+27H3-K84.3:14";
      =     "DB_DIGIT".SM.G81_MT34_1_L1;
      U     "DB_DIGIT".SM.G81_MT34_1_L1;
      NOT   ;
      U     #RelErrorCL;
      U     #RelErrorCR;
      =     "DB_DIGIT".FM.G81_MT34_1_L1;
NETWORK
TITLE ==81MT34-B84.1 FROST PROTECTION ALARM

      U     #ErrorConfirm;
      R     "DB_DIGIT".FM.G81_MT34_1_L2;
      U     "R27-81MT34+27H3-K84.4:14";
      =     "DB_DIGIT".SM.G81_MT34_1_L2;
      U     "DB_DIGIT".SM.G81_MT34_1_L2;
      NOT   ;
      U     #RelErrorCL;
      U     #RelErrorCR;
      S     "DB_DIGIT".FM.G81_MT34_1_L2;
      NOP   0;
NETWORK
TITLE ==81MT34-B84 FROST PROTECTION PLAUSIBILITY FAULT

      U     #ErrorConfirm;
      R     "DB_DIGIT".FM.G81_MT34_1_PLAUS;
      U     "DB_DIGIT".FM.G81_MT34_1_L2;
      UN    "DB_DIGIT".FM.G81_MT34_1_L1;
      U     #RelErrorCL;
      U     #RelErrorCR;
      S     "DB_DIGIT".FM.G81_MT34_1_PLAUS;
      NOP   0;
NETWORK
TITLE ==81PP40-M1 CONTROL/ERROR RELEASE

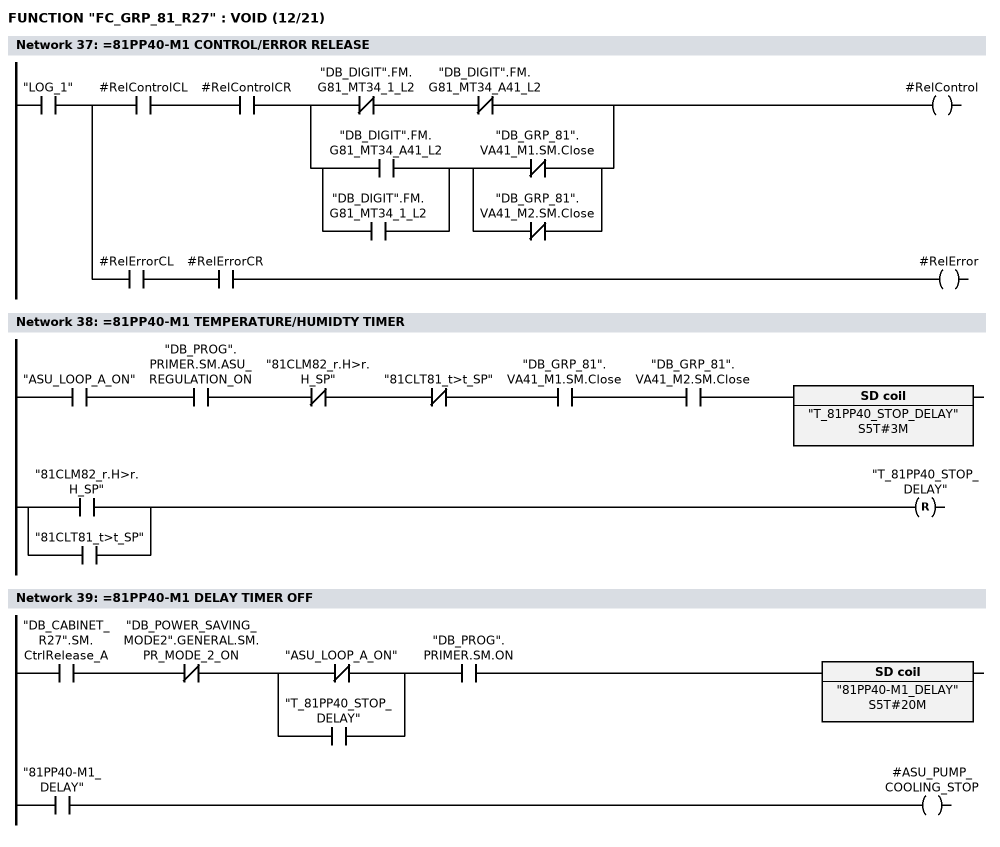
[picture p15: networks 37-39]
      U     "LOG_1";
      =     L     20.0;
      U     L     20.0;
      U     #RelControlCL;
      U     #RelControlCR;
      U(    ;
      UN    "DB_DIGIT".FM.G81_MT34_1_L2;
      UN    "DB_DIGIT".FM.G81_MT34_A41_L2;
      O     ;
      U(    ;
      O     "DB_DIGIT".FM.G81_MT34_A41_L2;
      O     "DB_DIGIT".FM.G81_MT34_1_L2;
      )     ;
      U(    ;
      ON    "DB_GRP_81".VA41_M1.SM.Close;
      ON    "DB_GRP_81".VA41_M2.SM.Close;
      )     ;
      )     ;
      =     #RelControl;
      U     L     20.0;
      U     #RelErrorCL;
      U     #RelErrorCR;
      =     #RelError;
NETWORK
TITLE ==81PP40-M1 TEMPERATURE/HUMIDTY TIMER

      U     "ASU_LOOP_A_ON";
      U     "DB_PROG".PRIMER.SM.ASU_REGULATION_ON;
      UN    "81CLM82_r.H>r.H_SP";
      UN    "81CLT81_t>t_SP";
      U     "DB_GRP_81".VA41_M1.SM.Close;
      U     "DB_GRP_81".VA41_M2.SM.Close;
      L     S5T#3M;
      SE    "T_81PP40_STOP_DELAY";
      U(    ;
      O     "81CLM82_r.H>r.H_SP";
      O     "81CLT81_t>t_SP";
      )     ;
      R     "T_81PP40_STOP_DELAY";
      NOP   0;
      NOP   0;
      NOP   0;
NETWORK
TITLE ==81PP40-M1 DELAY TIMER OFF

      U     "DB_CABINET_R27".SM.CtrlRelease_A;
      UN    "DB_POWER_SAVING_MODE2".GENERAL.SM.PR_MODE_2_ON;
      U(    ;
      ON    "ASU_LOOP_A_ON";
      O     "T_81PP40_STOP_DELAY";
      )     ;
      U     "DB_PROG".PRIMER.SM.ON;
      L     S5T#20M;
      SE    "81PP40-M1_DELAY";
      NOP   0;
      NOP   0;
      NOP   0;
      U     "81PP40-M1_DELAY";
      =     #ASU_PUMP_COOLING_STOP;
NETWORK
TITLE ==81PP40-M1 CONTROL SIGNALS

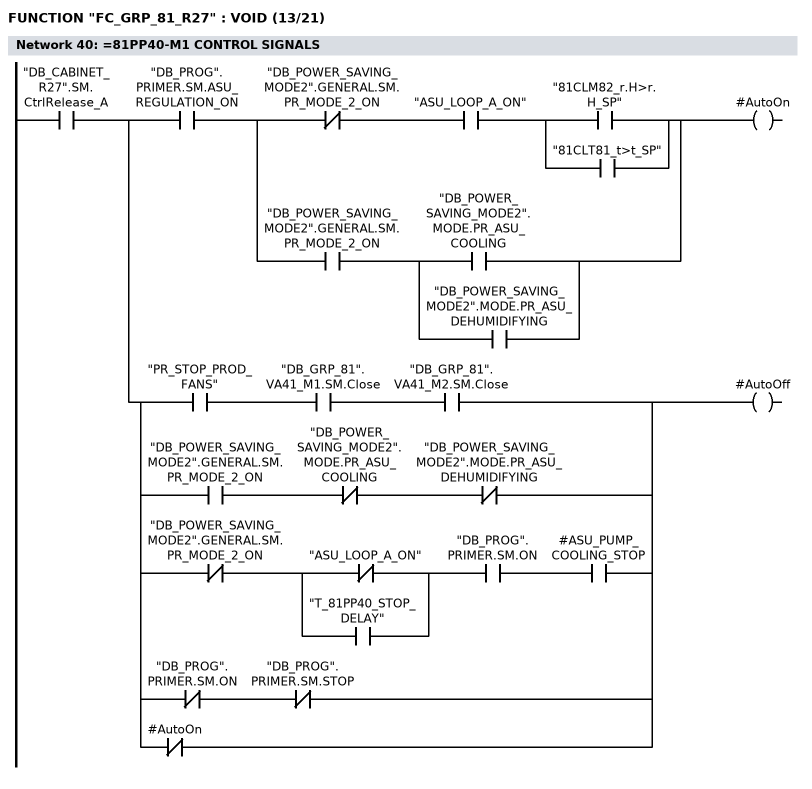
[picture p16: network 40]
      U     "DB_CABINET_R27".SM.CtrlRelease_A;
      =     L     20.0;
      U     L     20.0;
      U     "DB_PROG".PRIMER.SM.ASU_REGULATION_ON;
      U(    ;
      UN    "DB_POWER_SAVING_MODE2".GENERAL.SM.PR_MODE_2_ON;
      U     "ASU_LOOP_A_ON";
      U(    ;
      O     "81CLM82_r.H>r.H_SP";
      O     "81CLT81_t>t_SP";
      )     ;
      O     ;
      U     "DB_POWER_SAVING_MODE2".GENERAL.SM.PR_MODE_2_ON;
      U(    ;
      O     "DB_POWER_SAVING_MODE2".MODE.PR_ASU_COOLING;
      O     "DB_POWER_SAVING_MODE2".MODE.PR_ASU_DEHUMIDIFYING;
      )     ;
      )     ;
      =     #AutoOn;
      U     L     20.0;
      U(    ;
      U     "PR_STOP_PROD_FANS";
      U     "DB_GRP_81".VA41_M1.SM.Close;
      U     "DB_GRP_81".VA41_M2.SM.Close;
      O     ;
      U     "DB_POWER_SAVING_MODE2".GENERAL.SM.PR_MODE_2_ON;
      UN    "DB_POWER_SAVING_MODE2".MODE.PR_ASU_COOLING;
      UN    "DB_POWER_SAVING_MODE2".MODE.PR_ASU_DEHUMIDIFYING;
      O     ;
      UN    "DB_POWER_SAVING_MODE2".GENERAL.SM.PR_MODE_2_ON;
      U(    ;
      ON    "ASU_LOOP_A_ON";
      O     "T_81PP40_STOP_DELAY";
      )     ;
      U     "DB_PROG".PRIMER.SM.ON;
      U     #ASU_PUMP_COOLING_STOP;
      O     ;
      UN    "DB_PROG".PRIMER.SM.ON;
      UN    "DB_PROG".PRIMER.SM.STOP;
      ON    #AutoOn;
      )     ;
      =     #AutoOff;
NETWORK
TITLE ==81PP40-M1 PUMP COOLING

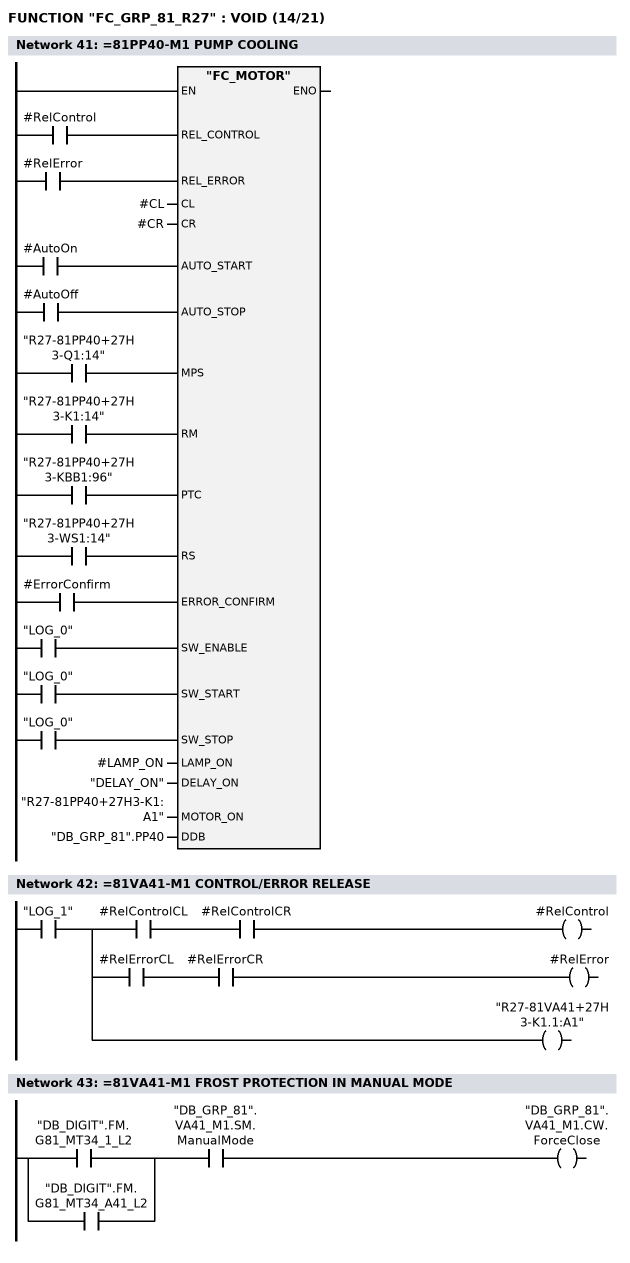
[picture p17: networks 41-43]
      U     #RelControl;
      =     L     20.0;
      BLD   103;
      U     #RelError;
      =     L     20.1;
      BLD   103;
      U     #AutoOn;
      =     L     20.2;
      BLD   103;
      U     #AutoOff;
      =     L     20.3;
      BLD   103;
      U     "R27-81PP40+27H3-Q1:14";
      =     L     20.4;
      BLD   103;
      U     "R27-81PP40+27H3-K1:14";
      =     L     20.5;
      BLD   103;
      U     "R27-81PP40+27H3-KBB1:96";
      =     L     20.6;
      BLD   103;
      U     "R27-81PP40+27H3-WS1:14";
      =     L     20.7;
      BLD   103;
      U     #ErrorConfirm;
      =     L     21.0;
      BLD   103;
      U     "LOG_0";
      =     L     21.1;
      BLD   103;
      U     "LOG_0";
      =     L     21.2;
      BLD   103;
      U     "LOG_0";
      =     L     21.3;
      BLD   103;
      CALL "FC_MOTOR" (
           REL_CONTROL              := L     20.0,
           REL_ERROR                := L     20.1,
           CL                       := #CL,
           CR                       := #CR,
           AUTO_START               := L     20.2,
           AUTO_STOP                := L     20.3,
           MPS                      := L     20.4,
           RM                       := L     20.5,
           PTC                      := L     20.6,
           RS                       := L     20.7,
           ERROR_CONFIRM            := L     21.0,
           SW_ENABLE                := L     21.1,
           SW_START                 := L     21.2,
           SW_STOP                  := L     21.3,
           LAMP_ON                  := #LAMP_ON,
           DELAY_ON                 := "DELAY_ON",
           MOTOR_ON                 := "R27-81PP40+27H3-K1:A1",
           DDB                      := "DB_GRP_81".PP40);
      NOP   0;
NETWORK
TITLE ==81VA41-M1 CONTROL/ERROR RELEASE

      U     "LOG_1";
      =     L     20.0;
      U     L     20.0;
      U     #RelControlCL;
      U     #RelControlCR;
      =     #RelControl;
      U     L     20.0;
      U     #RelErrorCL;
      U     #RelErrorCR;
      =     #RelError;
      U     L     20.0;
      BLD   102;
      =     "R27-81VA41+27H3-K1.1:A1";
NETWORK
TITLE ==81VA41-M1 FROST PROTECTION IN MANUAL MODE

      U(    ;
      O     "DB_DIGIT".FM.G81_MT34_1_L2;
      O     "DB_DIGIT".FM.G81_MT34_A41_L2;
      )     ;
      U     "DB_GRP_81".VA41_M1.SM.ManualMode;
      =     "DB_GRP_81".VA41_M1.CW.ForceClose;
NETWORK
TITLE =

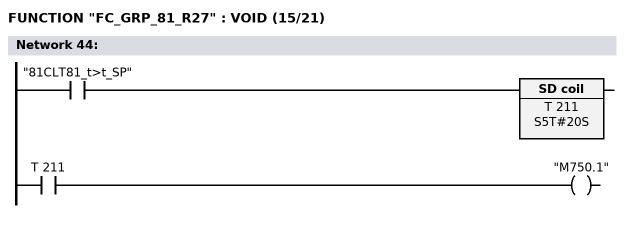
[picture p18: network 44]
      U     "81CLT81_t>t_SP";
      L     S5T#20S;
      SE    T    211;
      NOP   0;
      NOP   0;
      NOP   0;
      U     T    211;
      =     "M750.1";
NETWORK
TITLE ==81VA41-M1 CONTROL SIGNALS

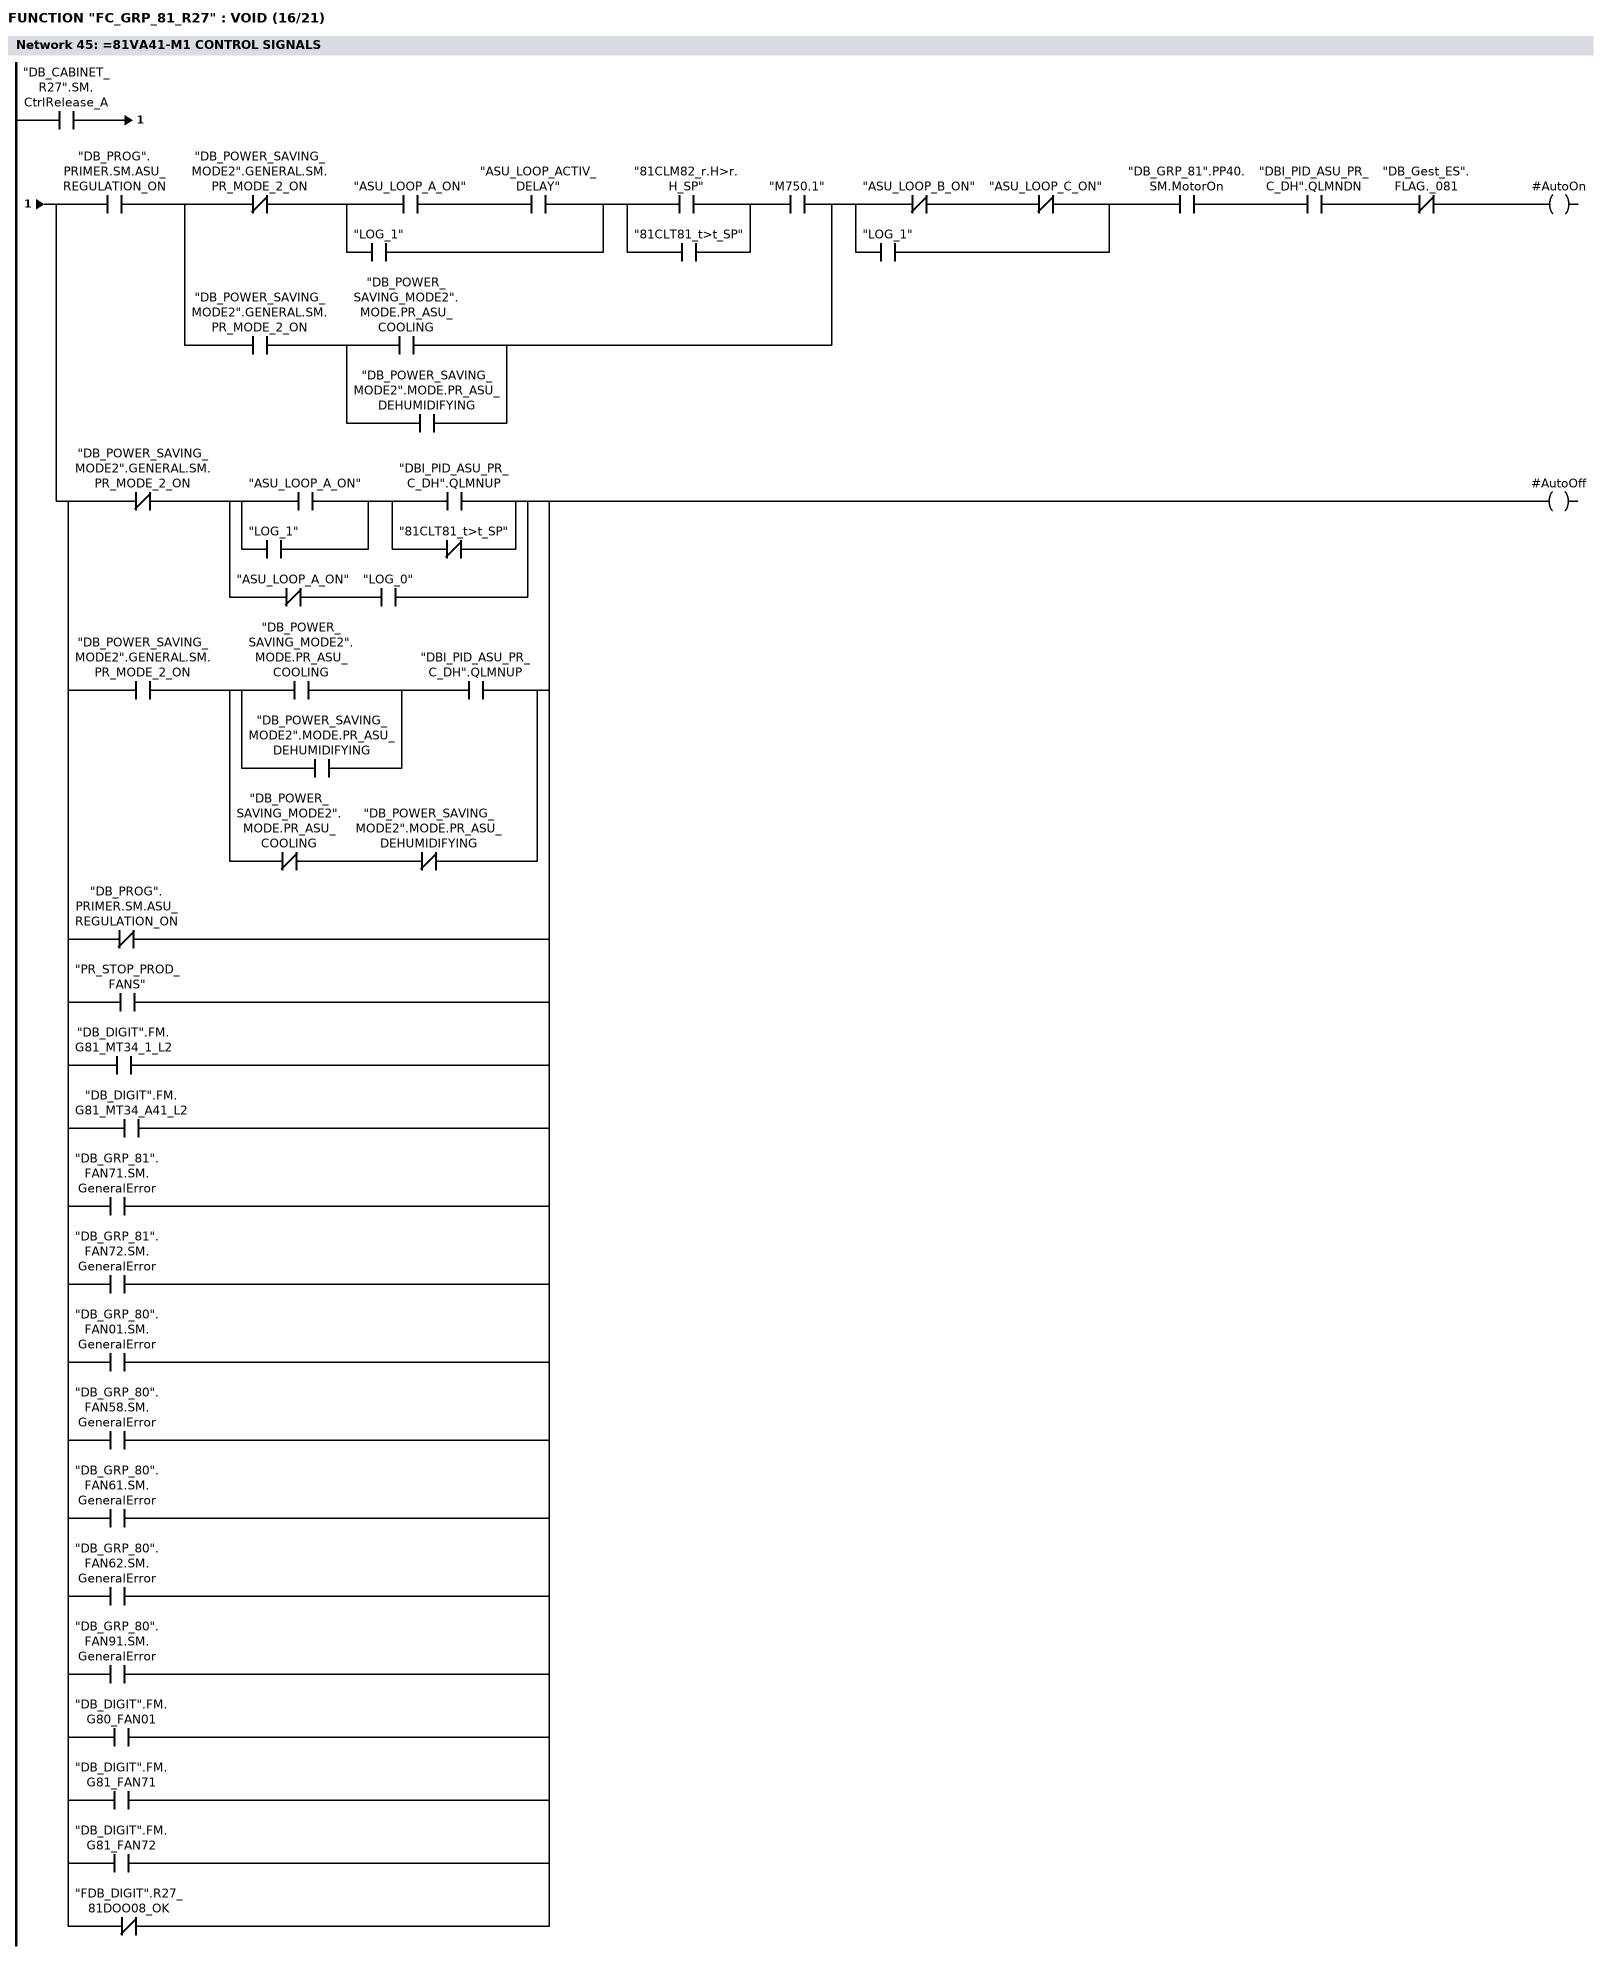
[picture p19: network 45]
      U     "DB_CABINET_R27".SM.CtrlRelease_A;
      =     L     20.0;
      U     L     20.0;
      U     "DB_PROG".PRIMER.SM.ASU_REGULATION_ON;
      U(    ;
      UN    "DB_POWER_SAVING_MODE2".GENERAL.SM.PR_MODE_2_ON;
      U(    ;
      U     "ASU_LOOP_A_ON";
      U     "ASU_LOOP_ACTIV_DELAY";
      O     "LOG_1";
      )     ;
      U(    ;
      O     "81CLM82_r.H>r.H_SP";
      O     "81CLT81_t>t_SP";
      )     ;
      U     "M750.1";
      O     ;
      U     "DB_POWER_SAVING_MODE2".GENERAL.SM.PR_MODE_2_ON;
      U(    ;
      O     "DB_POWER_SAVING_MODE2".MODE.PR_ASU_COOLING;
      O     "DB_POWER_SAVING_MODE2".MODE.PR_ASU_DEHUMIDIFYING;
      )     ;
      )     ;
      U(    ;
      UN    "ASU_LOOP_B_ON";
      UN    "ASU_LOOP_C_ON";
      O     "LOG_1";
      )     ;
      U     "DB_GRP_81".PP40.SM.MotorOn;
      U     "DBI_PID_ASU_PR_C_DH".QLMNDN;
      UN    "DB_Gest_ES".FLAG._081;
      =     #AutoOn;
      U     L     20.0;
      U(    ;
      UN    "DB_POWER_SAVING_MODE2".GENERAL.SM.PR_MODE_2_ON;
      U(    ;
      U(    ;
      O     "ASU_LOOP_A_ON";
      O     "LOG_1";
      )     ;
      U(    ;
      O     "DBI_PID_ASU_PR_C_DH".QLMNUP;
      ON    "81CLT81_t>t_SP";
      )     ;
      O     ;
      UN    "ASU_LOOP_A_ON";
      U     "LOG_0";
      )     ;
      O     ;
      U     "DB_POWER_SAVING_MODE2".GENERAL.SM.PR_MODE_2_ON;
      U(    ;
      U(    ;
      O     "DB_POWER_SAVING_MODE2".MODE.PR_ASU_COOLING;
      O     "DB_POWER_SAVING_MODE2".MODE.PR_ASU_DEHUMIDIFYING;
      )     ;
      U     "DBI_PID_ASU_PR_C_DH".QLMNUP;
      O     ;
      UN    "DB_POWER_SAVING_MODE2".MODE.PR_ASU_COOLING;
      UN    "DB_POWER_SAVING_MODE2".MODE.PR_ASU_DEHUMIDIFYING;
      )     ;
      ON    "DB_PROG".PRIMER.SM.ASU_REGULATION_ON;
      O     "PR_STOP_PROD_FANS";
      O     "DB_DIGIT".FM.G81_MT34_1_L2;
      O     "DB_DIGIT".FM.G81_MT34_A41_L2;
      O     "DB_GRP_81".FAN71.SM.GeneralError;
      O     "DB_GRP_81".FAN72.SM.GeneralError;
      O     "DB_GRP_80".FAN01.SM.GeneralError;
      O     "DB_GRP_80".FAN58.SM.GeneralError;
      O     "DB_GRP_80".FAN61.SM.GeneralError;
      O     "DB_GRP_80".FAN62.SM.GeneralError;
      O     "DB_GRP_80".FAN91.SM.GeneralError;
      O     "DB_DIGIT".FM.G80_FAN01;
      O     "DB_DIGIT".FM.G81_FAN71;
      O     "DB_DIGIT".FM.G81_FAN72;
      ON    "FDB_DIGIT".R27_81DOO08_OK;
      )     ;
      =     #AutoOff;
NETWORK
TITLE =AIR SUPPLY UNIT CONTROL LOOP A ACTIVE

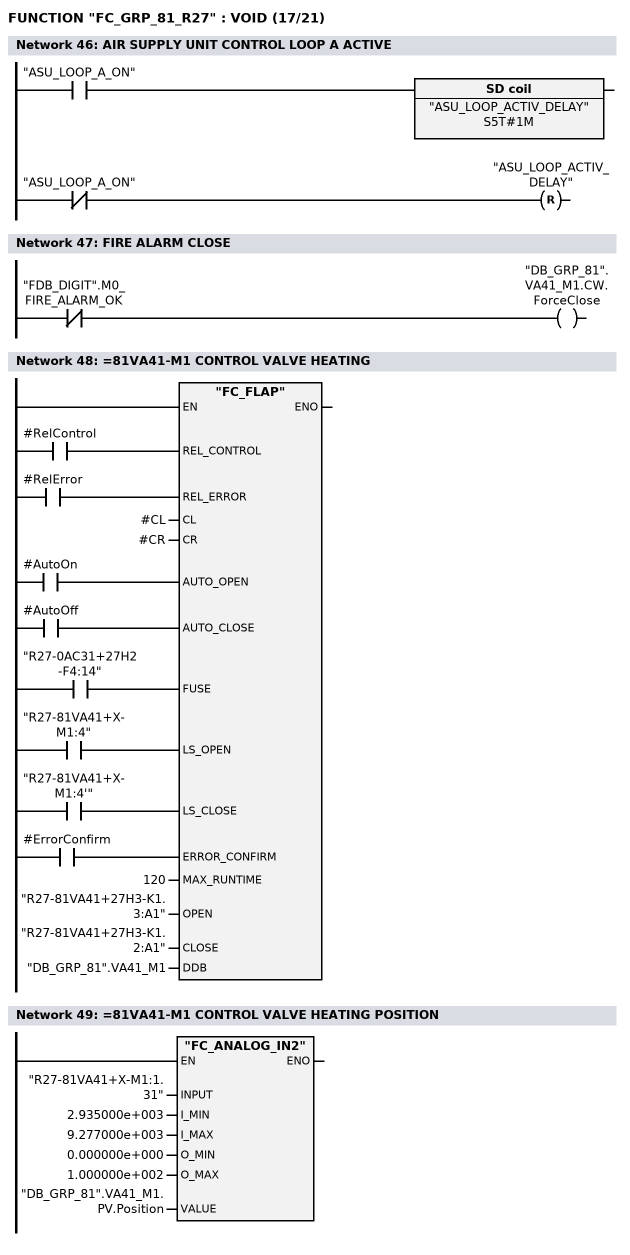
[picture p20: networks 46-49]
      U     "ASU_LOOP_A_ON";
      L     S5T#1M;
      SE    "ASU_LOOP_ACTIV_DELAY";
      UN    "ASU_LOOP_A_ON";
      R     "ASU_LOOP_ACTIV_DELAY";
      NOP   0;
      NOP   0;
      NOP   0;
NETWORK
TITLE =FIRE ALARM CLOSE

      UN    "FDB_DIGIT".M0_FIRE_ALARM_OK;
      =     "DB_GRP_81".VA41_M1.CW.ForceClose;
NETWORK
TITLE ==81VA41-M1 CONTROL VALVE HEATING

      U     #RelControl;
      =     L     20.0;
      BLD   103;
      U     #RelError;
      =     L     20.1;
      BLD   103;
      U     #AutoOn;
      =     L     20.2;
      BLD   103;
      U     #AutoOff;
      =     L     20.3;
      BLD   103;
      U     "R27-0AC31+27H2-F4:14";
      =     L     20.4;
      BLD   103;
      U     "R27-81VA41+X-M1:4";
      =     L     20.5;
      BLD   103;
      U     "R27-81VA41+X-M1:4'";
      =     L     20.6;
      BLD   103;
      U     #ErrorConfirm;
      =     L     20.7;
      BLD   103;
      CALL "FC_FLAP" (
           REL_CONTROL              := L     20.0,
           REL_ERROR                := L     20.1,
           CL                       := #CL,
           CR                       := #CR,
           AUTO_OPEN                := L     20.2,
           AUTO_CLOSE               := L     20.3,
           FUSE                     := L     20.4,
           LS_OPEN                  := L     20.5,
           LS_CLOSE                 := L     20.6,
           ERROR_CONFIRM            := L     20.7,
           MAX_RUNTIME              := 120,
           OPEN                     := "R27-81VA41+27H3-K1.3:A1",
           CLOSE                    := "R27-81VA41+27H3-K1.2:A1",
           DDB                      := "DB_GRP_81".VA41_M1);
      NOP   0;
NETWORK
TITLE ==81VA41-M1 CONTROL VALVE HEATING POSITION

      CALL "FC_ANALOG_IN2" (
           INPUT                    := "R27-81VA41+X-M1:1.31",
           I_MIN                    := 2.935000e+003,
           I_MAX                    := 9.277000e+003,
           O_MIN                    := 0.000000e+000,
           O_MAX                    := 1.000000e+002,
           VALUE                    := "DB_GRP_81".VA41_M1.PV.Position);
      NOP   0;
NETWORK
TITLE ==81VA41-M2 CONTROL/ERROR RELEASE

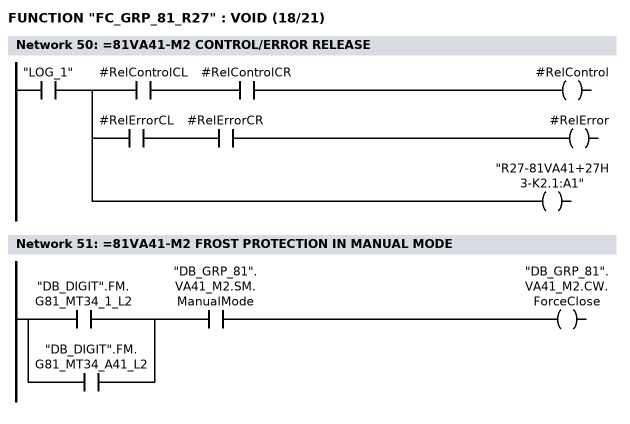
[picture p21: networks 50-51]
      U     "LOG_1";
      =     L     20.0;
      U     L     20.0;
      U     #RelControlCL;
      U     #RelControlCR;
      =     #RelControl;
      U     L     20.0;
      U     #RelErrorCL;
      U     #RelErrorCR;
      =     #RelError;
      U     L     20.0;
      BLD   102;
      =     "R27-81VA41+27H3-K2.1:A1";
NETWORK
TITLE ==81VA41-M2 FROST PROTECTION IN MANUAL MODE

      U(    ;
      O     "DB_DIGIT".FM.G81_MT34_1_L2;
      O     "DB_DIGIT".FM.G81_MT34_A41_L2;
      )     ;
      U     "DB_GRP_81".VA41_M2.SM.ManualMode;
      =     "DB_GRP_81".VA41_M2.CW.ForceClose;
NETWORK
TITLE ==81VA41-M2 CONTROL VALVE HEATING CONTROL SIGNALS

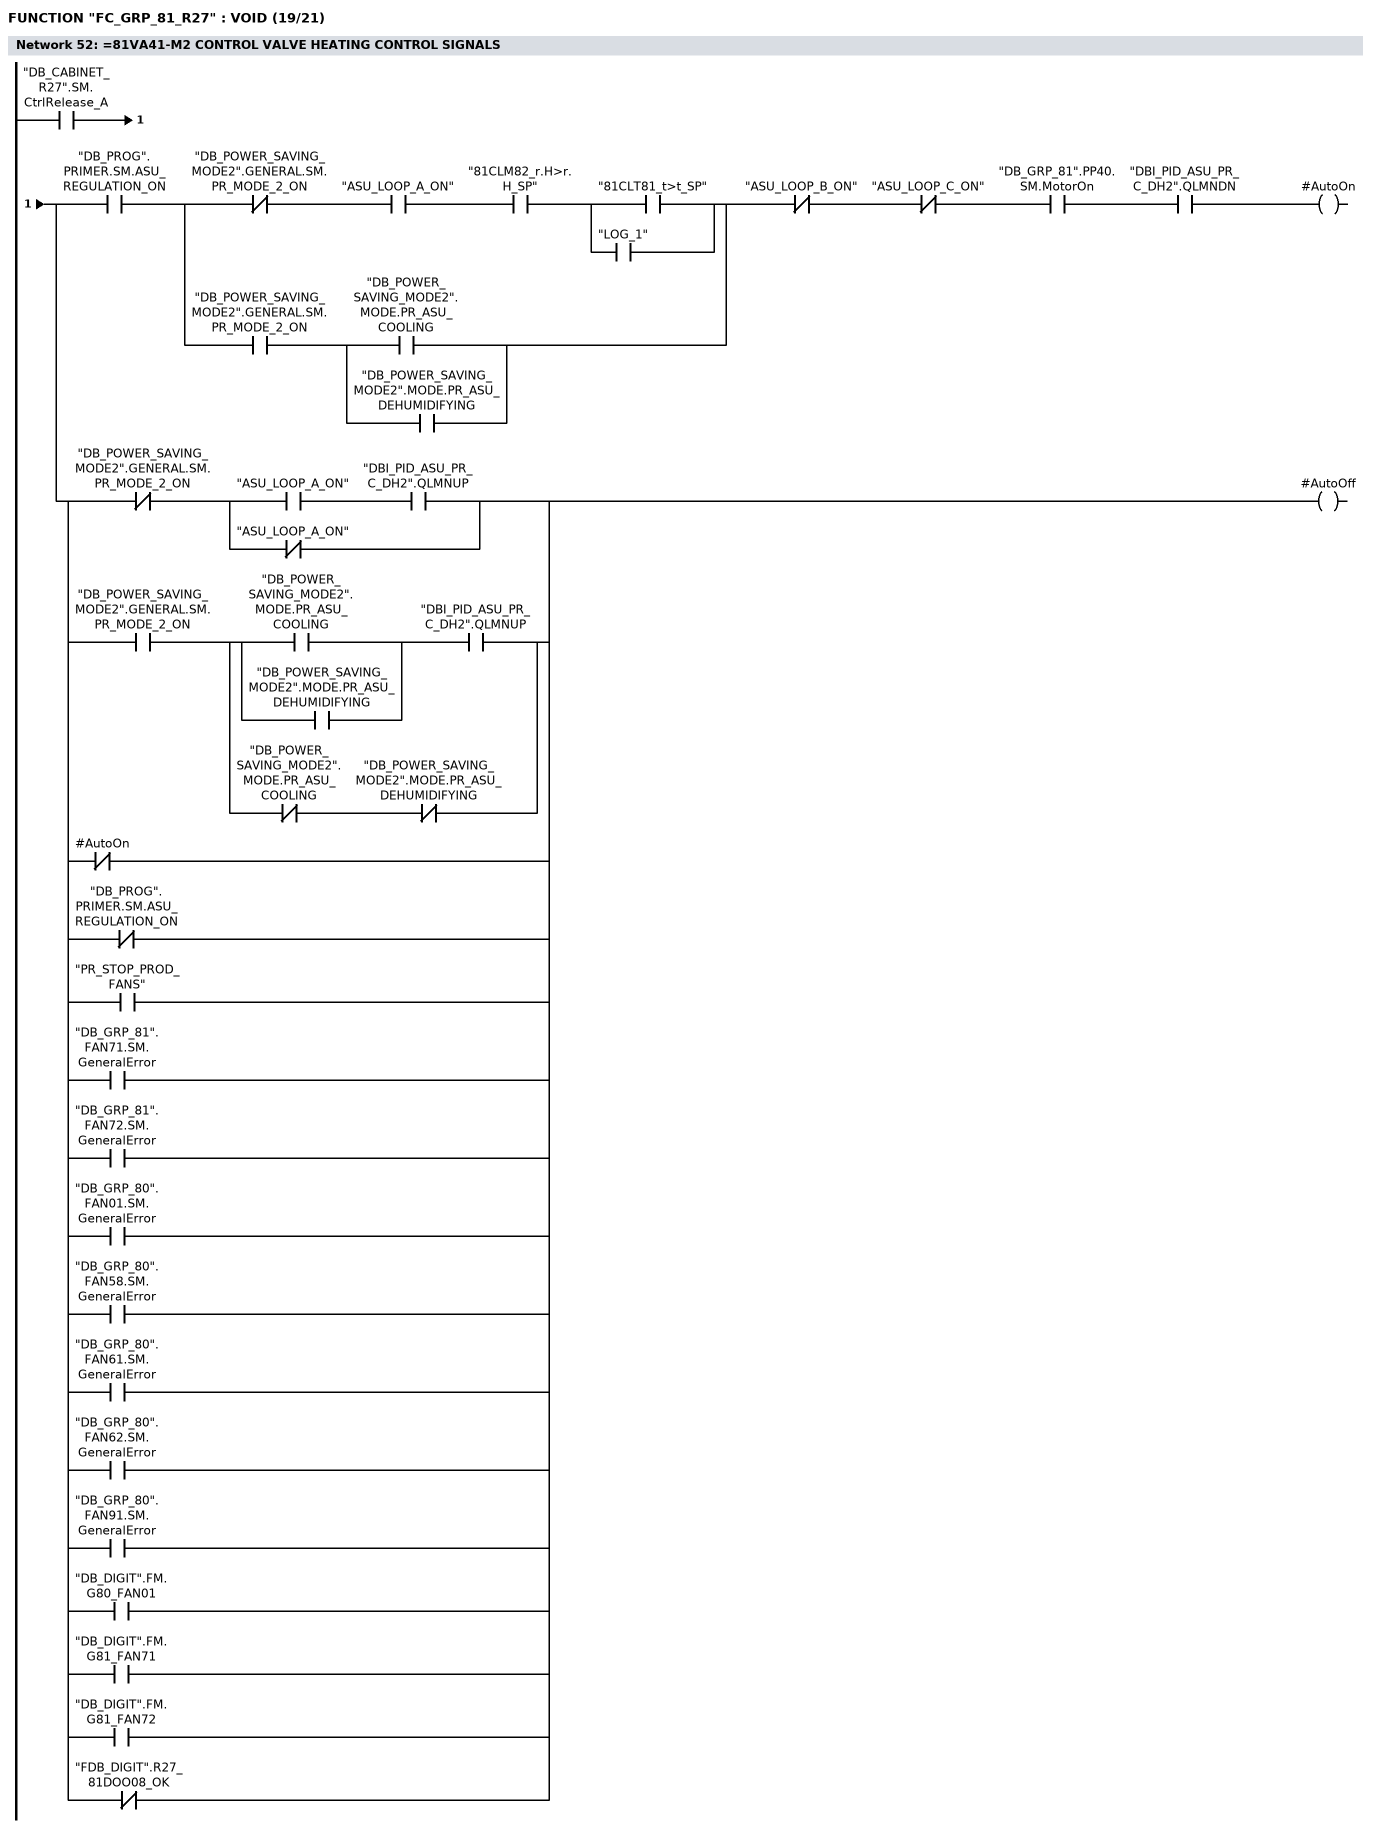
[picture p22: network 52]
      U     "DB_CABINET_R27".SM.CtrlRelease_A;
      =     L     20.0;
      U     L     20.0;
      U     "DB_PROG".PRIMER.SM.ASU_REGULATION_ON;
      U(    ;
      UN    "DB_POWER_SAVING_MODE2".GENERAL.SM.PR_MODE_2_ON;
      U     "ASU_LOOP_A_ON";
      U     "81CLM82_r.H>r.H_SP";
      U(    ;
      O     "81CLT81_t>t_SP";
      O     "LOG_1";
      )     ;
      O     ;
      U     "DB_POWER_SAVING_MODE2".GENERAL.SM.PR_MODE_2_ON;
      U(    ;
      O     "DB_POWER_SAVING_MODE2".MODE.PR_ASU_COOLING;
      O     "DB_POWER_SAVING_MODE2".MODE.PR_ASU_DEHUMIDIFYING;
      )     ;
      )     ;
      UN    "ASU_LOOP_B_ON";
      UN    "ASU_LOOP_C_ON";
      U     "DB_GRP_81".PP40.SM.MotorOn;
      U     "DBI_PID_ASU_PR_C_DH2".QLMNDN;
      =     #AutoOn;
      U     L     20.0;
      U(    ;
      UN    "DB_POWER_SAVING_MODE2".GENERAL.SM.PR_MODE_2_ON;
      U(    ;
      U     "ASU_LOOP_A_ON";
      U     "DBI_PID_ASU_PR_C_DH2".QLMNUP;
      ON    "ASU_LOOP_A_ON";
      )     ;
      O     ;
      U     "DB_POWER_SAVING_MODE2".GENERAL.SM.PR_MODE_2_ON;
      U(    ;
      U(    ;
      O     "DB_POWER_SAVING_MODE2".MODE.PR_ASU_COOLING;
      O     "DB_POWER_SAVING_MODE2".MODE.PR_ASU_DEHUMIDIFYING;
      )     ;
      U     "DBI_PID_ASU_PR_C_DH2".QLMNUP;
      O     ;
      UN    "DB_POWER_SAVING_MODE2".MODE.PR_ASU_COOLING;
      UN    "DB_POWER_SAVING_MODE2".MODE.PR_ASU_DEHUMIDIFYING;
      )     ;
      ON    #AutoOn;
      ON    "DB_PROG".PRIMER.SM.ASU_REGULATION_ON;
      O     "PR_STOP_PROD_FANS";
      O     "DB_GRP_81".FAN71.SM.GeneralError;
      O     "DB_GRP_81".FAN72.SM.GeneralError;
      O     "DB_GRP_80".FAN01.SM.GeneralError;
      O     "DB_GRP_80".FAN58.SM.GeneralError;
      O     "DB_GRP_80".FAN61.SM.GeneralError;
      O     "DB_GRP_80".FAN62.SM.GeneralError;
      O     "DB_GRP_80".FAN91.SM.GeneralError;
      O     "DB_DIGIT".FM.G80_FAN01;
      O     "DB_DIGIT".FM.G81_FAN71;
      O     "DB_DIGIT".FM.G81_FAN72;
      ON    "FDB_DIGIT".R27_81DOO08_OK;
      )     ;
      =     #AutoOff;
NETWORK
TITLE =FIRE ALARM CLOSE

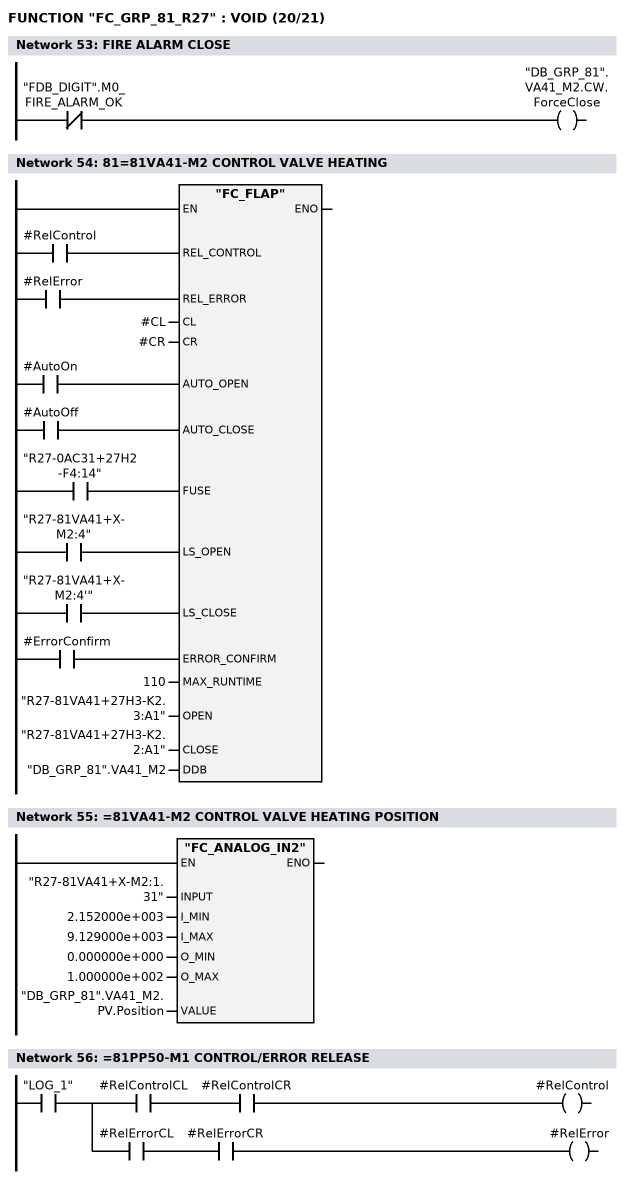
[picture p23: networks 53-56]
      UN    "FDB_DIGIT".M0_FIRE_ALARM_OK;
      =     "DB_GRP_81".VA41_M2.CW.ForceClose;
NETWORK
TITLE =81=81VA41-M2 CONTROL VALVE HEATING

      U     #RelControl;
      =     L     20.0;
      BLD   103;
      U     #RelError;
      =     L     20.1;
      BLD   103;
      U     #AutoOn;
      =     L     20.2;
      BLD   103;
      U     #AutoOff;
      =     L     20.3;
      BLD   103;
      U     "R27-0AC31+27H2-F4:14";
      =     L     20.4;
      BLD   103;
      U     "R27-81VA41+X-M2:4";
      =     L     20.5;
      BLD   103;
      U     "R27-81VA41+X-M2:4'";
      =     L     20.6;
      BLD   103;
      U     #ErrorConfirm;
      =     L     20.7;
      BLD   103;
      CALL "FC_FLAP" (
           REL_CONTROL              := L     20.0,
           REL_ERROR                := L     20.1,
           CL                       := #CL,
           CR                       := #CR,
           AUTO_OPEN                := L     20.2,
           AUTO_CLOSE               := L     20.3,
           FUSE                     := L     20.4,
           LS_OPEN                  := L     20.5,
           LS_CLOSE                 := L     20.6,
           ERROR_CONFIRM            := L     20.7,
           MAX_RUNTIME              := 110,
           OPEN                     := "R27-81VA41+27H3-K2.3:A1",
           CLOSE                    := "R27-81VA41+27H3-K2.2:A1",
           DDB                      := "DB_GRP_81".VA41_M2);
      NOP   0;
NETWORK
TITLE ==81VA41-M2 CONTROL VALVE HEATING POSITION

      CALL "FC_ANALOG_IN2" (
           INPUT                    := "R27-81VA41+X-M2:1.31",
           I_MIN                    := 2.152000e+003,
           I_MAX                    := 9.129000e+003,
           O_MIN                    := 0.000000e+000,
           O_MAX                    := 1.000000e+002,
           VALUE                    := "DB_GRP_81".VA41_M2.PV.Position);
      NOP   0;
NETWORK
TITLE ==81PP50-M1 CONTROL/ERROR RELEASE

      U     "LOG_1";
      =     L     20.0;
      U     L     20.0;
      U     #RelControlCL;
      U     #RelControlCR;
      =     #RelControl;
      U     L     20.0;
      U     #RelErrorCL;
      U     #RelErrorCR;
      =     #RelError;
NETWORK
TITLE ==81PP50/51 TEMPERATURE TIMER

      U     "DB_PROG".PRIMER.SM.ASU_REGULATION_ON;
      U     "ASU_LOOP_C_ON";
      U     "81CLT81_t>t_SP";
      U     "DB_GRP_81".VA51.SM.Open;
      U(    ;
      L     "DB_GRP_81".PP51.PV.SP;
      L     7.500000e+000;
      <=R   ;
      )     ;
      L     S5T#3M;
      SE    "T_81PP50_51_STOP_DELAY";
      U(    ;
      ON    "81CLT81_t>t_SP";
      ON    "ASU_LOOP_C_ON";
      ON    "DB_PROG".PRIMER.SM.ASU_REGULATION_ON;
      )     ;
      R     "T_81PP50_51_STOP_DELAY";
      NOP   0;
      NOP   0;
      NOP   0;
NETWORK
TITLE =

      U     "LOG_1";
      =     L     20.0;
      U     L     20.0;
      U(    ;
      L     "DB_GRP_81".CLM82_HUM.PV.AV;
      L     "DB_GRP_81".CLM82_HUM.PV.SP_AV;
      <=R   ;
      )     ;
      L     S5T#30S;
      SE    T    215;
      NOP   0;
      NOP   0;
      NOP   0;
      U     T    215;
      =     "M750.5";
      U(    ;
      U     L     20.0;
      SPBNB _003;
      L     "DB_GRP_81".CLM82_HUM.PV.SP_AV;
      L     "DB_SETPOINTS".HUM_81CLM82_HUM_SP;
      +R    ;
      T     #H_81CLM82_HUM_SWP;
      UN    OV;
      SAVE  ;
      CLR   ;
_003: U     BIE;
      )     ;
      U(    ;
      L     "DB_GRP_81".CLM82_HUM.PV.AV;
      L     #H_81CLM82_HUM_SWP;
      >=R   ;
      )     ;
      L     S5T#30S;
      SE    T    216;
      NOP   0;
      NOP   0;
      NOP   0;
      U     T    216;
      =     "M750.6";
      U     L     20.0;
      U(    ;
      L     "DB_GRP_81".CLT81.PV.AV;
      L     "DB_GRP_81".CLT81.PV.SP_AV;
      <R    ;
      )     ;
      L     S5T#15S;
      SE    T    217;
      NOP   0;
      NOP   0;
      NOP   0;
      U     T    217;
      =     "M750.7";
      U(    ;
      U     L     20.0;
      SPBNB _004;
      L     "DB_GRP_81".CLT81.PV.SP_AV;
      L     "DB_SETPOINTS".TEMP_81CL81_HEAT_SP;
      -R    ;
      T     #T_81CLT81_HEAT_SWP;
      UN    OV;
      SAVE  ;
      CLR   ;
_004: U     BIE;
      )     ;
      U(    ;
      L     "DB_GRP_81".CLT81.PV.AV;
      L     #T_81CLT81_HEAT_SWP;
      <R    ;
      )     ;
      L     S5T#15S;
      SE    T    218;
      NOP   0;
      NOP   0;
      NOP   0;
      U     T    218;
      =     "M751.0";
      U     L     20.0;
      SPBNB _005;
      L     "DB_GRP_81".CLT81.PV.SP_AV;
      L     "DB_SETPOINTS".TEMP_81CL81_HEAT_SP;
      +R    ;
      T     #T_81CLT81_HEAT_SWP_MAX;
_005: NOP   0;
      U     L     20.0;
      U(    ;
      L     "DB_GRP_81".CLT32.PV.AV;
      L     #T_81CLT81_HEAT_SWP;
      >=R   ;
      )     ;
      U(    ;
      L     "DB_GRP_81".CLT32.PV.AV;
      L     #T_81CLT81_HEAT_SWP_MAX;
      <=R   ;
      )     ;
      L     S5T#15S;
      SE    T    219;
      NOP   0;
      NOP   0;
      NOP   0;
      U     T    219;
      =     "M751.1";
NETWORK
TITLE ==81PP50-U1 CONTROL SIGNALS
//2016.07.09 SPH: Added "LOG_1" bypassing signal from not used valve
//"DB_GRP_81".VA51.SM.Open.
      U     "DB_CABINET_R27".SM.CtrlRelease_A;
      =     L     20.0;
      U     L     20.0;
      U     "DB_PROG".PRIMER.SM.ASU_REGULATION_ON;
      U     "DB_PROG".PRIMER.SM.ASU_ON;
      U(    ;
      UN    "DB_POWER_SAVING_MODE2".GENERAL.SM.PR_MODE_2_ON;
      U(    ;
      O     "ASU_LOOP_C_ON";
      O     "M750.6";
      O     "M750.7";
      )     ;
      UN    "81CLT81_t>t_SP";
      O     ;
      U     "DB_POWER_SAVING_MODE2".GENERAL.SM.PR_MODE_2_ON;
      U     "DB_POWER_SAVING_MODE2".MODE.PR_ASU_HEATING;
      )     ;
      UN    "DB_DIGIT".FM.G81_MT33;
      UN    "DB_DIGIT".FM.G81_MT53;
      UN    "DB_Gest_ES".FLAG._080;
      =     #AutoOn;
      U     L     20.0;
      U(    ;
      UN    "DB_POWER_SAVING_MODE2".GENERAL.SM.PR_MODE_2_ON;
      U(    ;
      O     "T_81PP50_51_STOP_DELAY";
      O     ;
      UN    "ASU_LOOP_C_ON";
      U     "M750.5";
      UN    "M750.7";
      )     ;
      O     ;
      U     "DB_POWER_SAVING_MODE2".GENERAL.SM.PR_MODE_2_ON;
      UN    "DB_POWER_SAVING_MODE2".MODE.PR_ASU_HEATING;
      ON    "DB_PROG".PRIMER.SM.ASU_REGULATION_ON;
      O     "DB_DIGIT".FM.G80_FAN01;
      O     "DB_DIGIT".FM.G81_FAN71;
      O     "DB_DIGIT".FM.G81_FAN72;
      ON    "FDB_DIGIT".R27_81DOO08_OK;
      O     "DB_GRP_80".FAN01.SM.GeneralError;
      O     "DB_GRP_80".FAN58.SM.GeneralError;
      O     "DB_GRP_80".FAN61.SM.GeneralError;
      O     "DB_GRP_80".FAN62.SM.GeneralError;
      O     "DB_GRP_80".FAN91.SM.GeneralError;
      O     "DB_GRP_81".FAN71.SM.GeneralError;
      O     "DB_GRP_81".FAN72.SM.GeneralError;
      O     "DB_Gest_ES".FLAG._080;
      O     ;
      U(    ;
      O     "DB_DIGIT".FM.G81_MT33;
      O     "DB_DIGIT".FM.G81_MT53;
      )     ;
      U     "DB_GRP_81".VA51.SM.Open;
      )     ;
      =     #AutoOff;
NETWORK
TITLE ==81PP50-M1 HEATING PUMP

      U     #RelControl;
      =     L     20.0;
      BLD   103;
      U     #RelError;
      =     L     20.1;
      BLD   103;
      U     #AutoOn;
      =     L     20.2;
      BLD   103;
      U     #AutoOff;
      =     L     20.3;
      BLD   103;
      U     "R27-81PP50+27H3-Q1:14";
      =     L     20.4;
      BLD   103;
      U     "R27-81PP50+27H3-K1:14";
      =     L     20.5;
      BLD   103;
      U     "R27-81PP50+27H3-KBB1:96";
      =     L     20.6;
      BLD   103;
      U     "R27-81PP50+27H3-WS1:14";
      =     L     20.7;
      BLD   103;
      U     #ErrorConfirm;
      =     L     21.0;
      BLD   103;
      U     "LOG_0";
      =     L     21.1;
      BLD   103;
      U     "LOG_0";
      =     L     21.2;
      BLD   103;
      U     "LOG_0";
      =     L     21.3;
      BLD   103;
      CALL "FC_MOTOR" (
           REL_CONTROL              := L     20.0,
           REL_ERROR                := L     20.1,
           CL                       := #CL,
           CR                       := #CR,
           AUTO_START               := L     20.2,
           AUTO_STOP                := L     20.3,
           MPS                      := L     20.4,
           RM                       := L     20.5,
           PTC                      := L     20.6,
           RS                       := L     20.7,
           ERROR_CONFIRM            := L     21.0,
           SW_ENABLE                := L     21.1,
           SW_START                 := L     21.2,
           SW_STOP                  := L     21.3,
           LAMP_ON                  := #LAMP_ON,
           DELAY_ON                 := "DELAY_ON",
           MOTOR_ON                 := "R27-81PP50+27H3-K1:A1",
           DDB                      := "DB_GRP_81".PP50);
      NOP   0;
NETWORK
TITLE ==81PP51-U1 CONTROL/ERROR RELEASE

      U     "LOG_1";
      =     L     20.0;
      U     L     20.0;
      U     #RelControlCL;
      U     #RelControlCR;
      =     #RelControl;
      U     L     20.0;
      U     #RelErrorCL;
      U     #RelErrorCR;
      =     #RelError;
NETWORK
TITLE =

      UN    "LOG_0";
      =     L     20.0;
      U     L     20.0;
      U     "81CLT81_t>t_SP";
      L     S5T#5S;
      SE    T    212;
      NOP   0;
      NOP   0;
      NOP   0;
      U     T    212;
      =     "M750.2";
      U     L     20.0;
      U     "81CLM82_r.H>r.H_SP_DEHUM";
      L     S5T#5S;
      SE    T    213;
      NOP   0;
      NOP   0;
      NOP   0;
      U     T    213;
      =     "M750.3";
NETWORK
TITLE ==81PP51-U1 CONTROL SIGNALS
//2016.07.09 SPH: Added "LOG_1" bypassing signal from not used valve
//"DB_GRP_81".VA51.SM.Open
      U     "DB_CABINET_R27".SM.CtrlRelease_A;
      =     L     20.0;
      U     L     20.0;
      U     "DB_PROG".PRIMER.SM.ASU_REGULATION_ON;
      U(    ;
      UN    "DB_POWER_SAVING_MODE2".GENERAL.SM.PR_MODE_2_ON;
      U(    ;
      U(    ;
      U     "LOG_0";
      U     "ASU_LOOP_C_ON";
      O     ;
      U     "LOG_0";
      U     "81CLM82_r.H>r.H_SP_DEHUM";
      O     ;
      U     "LOG_0";
      U     "M751.0";
      )     ;
      U(    ;
      UN    "M750.2";
      U     "M751.0";
      O     "M750.3";
      )     ;
      O     ;
      U     "ASU_LOOP_C_ON";
      UN    "81CLT81_t>t_SP";
      )     ;
      O     ;
      U     "DB_POWER_SAVING_MODE2".GENERAL.SM.PR_MODE_2_ON;
      U     "DB_POWER_SAVING_MODE2".MODE.PR_ASU_HEATING;
      )     ;
      U     "DB_GRP_81".PP50.SM.MotorOn;
      UN    "DB_DIGIT".FM.G81_MT33;
      UN    "DB_DIGIT".FM.G81_MT53;
      UN    "DB_Gest_ES".FLAG._080;
      =     #AutoOn;
      =     "81pp51";
      U     L     20.0;
      U(    ;
      UN    "DB_POWER_SAVING_MODE2".GENERAL.SM.PR_MODE_2_ON;
      U     "LOG_0";
      U(    ;
      O     "T_81PP50_51_STOP_DELAY";
      O     ;
      U     "M750.2";
      UN    "M750.3";
      O     ;
      UN    "ASU_LOOP_C_ON";
      UN    "M750.3";
      UN    "M751.0";
      )     ;
      O     ;
      U     "DB_POWER_SAVING_MODE2".GENERAL.SM.PR_MODE_2_ON;
      UN    "DB_POWER_SAVING_MODE2".MODE.PR_ASU_HEATING;
      ON    "DB_PROG".PRIMER.SM.ASU_REGULATION_ON;
      O     "DB_DIGIT".FM.G80_FAN01;
      O     "DB_DIGIT".FM.G81_FAN71;
      O     "DB_DIGIT".FM.G81_FAN72;
      ON    "FDB_DIGIT".R27_81DOO08_OK;
      O     "DB_GRP_80".FAN01.SM.GeneralError;
      O     "DB_GRP_80".FAN58.SM.GeneralError;
      O     "DB_GRP_80".FAN61.SM.GeneralError;
      O     "DB_GRP_80".FAN62.SM.GeneralError;
      O     "DB_GRP_80".FAN91.SM.GeneralError;
      O     "DB_GRP_81".FAN71.SM.GeneralError;
      O     "DB_GRP_81".FAN72.SM.GeneralError;
      O     ;
      U(    ;
      O     "DB_DIGIT".FM.G81_MT33;
      O     "DB_DIGIT".FM.G81_MT53;
      )     ;
      U     "DB_GRP_81".VA51.SM.Open;
      )     ;
      =     #AutoOff;
NETWORK
TITLE ==81PP51-U1 HEATING PUMP SETPOINT TRANSFER

      U     "LOG_1";
      U     "DB_GRP_81".PP51.SM.AutomaticMode;
      =     L     20.0;
      U     L     20.0;
      UN    "DB_GRP_81".PID_HEATING2.SM.CTRL_On;
      =     L     20.1;
      U     L     20.1;
      UN    "M751.0";
      SPBNB _006;
      L     6.500000e+000;
      T     "DB_GRP_81".PP51.PV.SP;
_006: NOP   0;
      U     L     20.1;
      U     "M751.0";
      SPBNB _007;
      L     1.500000e+001;
      T     "DB_GRP_81".PP51.PV.SP;
_007: NOP   0;
      U     L     20.0;
      UN    "81CLT81_t>t_SP";
      U     "DB_GRP_81".PID_HEATING2.SM.CTRL_On;
      SPBNB _008;
      L     "DB_GRP_81".PID_HEATING2.PV.ManipulatedVariable_AV;
      T     "DB_GRP_81".PP51.PV.SP;
_008: NOP   0;
NETWORK
TITLE =

      U     "R27-81PP51+X-U1-P7:2";
      =     M    100.0;
NETWORK
TITLE ==81PP51-U1 HEATING PUMP

      U     #RelControl;
      =     L     20.0;
      BLD   103;
      U     #RelError;
      =     L     20.1;
      BLD   103;
      U     #AutoOn;
      =     L     20.2;
      BLD   103;
      U     #AutoOff;
      =     L     20.3;
      BLD   103;
      U     "R27-81PP51+27H3-Q1:14";
      =     L     20.4;
      BLD   103;
      U     "R27-81PP51+27H3-WS1:14";
      =     L     20.5;
      BLD   103;
      U     "LOG_1";
      =     L     20.6;
      BLD   103;
      U     M    100.0;
      =     L     20.7;
      BLD   103;
      U     #ErrorConfirm;
      =     L     21.0;
      BLD   103;
      U     "LOG_0";
      =     L     21.1;
      BLD   103;
      U     "LOG_0";
      =     L     21.2;
      BLD   103;
      U     "LOG_0";
      =     L     21.3;
      BLD   103;
      CALL "FC_MOTOR_KSB" (
           REL_CONTROL              := L     20.0,
           REL_ERROR                := L     20.1,
           CL                       := #CL,
           CR                       := #CR,
           AUTO_START               := L     20.2,
           AUTO_STOP                := L     20.3,
           MPS                      := L     20.4,
           RS                       := L     20.5,
           PTC_WAR                  := L     20.6,
           GENERAL_ERROR            := L     20.7,
           ERROR_CONFIRM            := L     21.0,
           ACTUAL_SPEED             := "R27-81P51-27H3-FRQAV",
           MAX_TIME_RAMP            := 30,
           SW_ENABLE                := L     21.1,
           SW_START                 := L     21.2,
           SW_STOP                  := L     21.3,
           SP                       := "R27-81P51-27H3-FRQSP",
           RESET                    := "R27-81PP51+27H3-K1.1:A1",
           LAMP_ON                  := #LAMP_ON,
           DELAY_ON                 := "DELAY_ON",
           MOTOR_ON                 := "R27-81PP51+27H3-K1.2:A1",
           DDB                      := "DB_GRP_81".PP51);
      NOP   0;
NETWORK
TITLE ==81VA51-M1 CONTROL/ERROR RELEASE

      U     "LOG_1";
      =     L     20.0;
      U     L     20.0;
      U     #RelControlCL;
      U     #RelControlCR;
      =     #RelControl;
      U     L     20.0;
      U     #RelErrorCL;
      U     #RelErrorCR;
      =     #RelError;
NETWORK
TITLE ==81VA51-M1 CONTROL HEATING VALVE CONTROL SIGNALS

      U     "DB_CABINET_R27".SM.CtrlRelease_A;
      =     L     20.0;
      U     L     20.0;
      U(    ;
      U(    ;
      U     "DB_PROG".PRIMER.SM.ASU_REGULATION_ON;
      U(    ;
      UN    "DB_POWER_SAVING_MODE2".GENERAL.SM.PR_MODE_2_ON;
      U     "ASU_LOOP_C_ON";
      UN    "81CLT81_t>t_SP";
      UN    "81pp51";
      O     ;
      U     "DB_POWER_SAVING_MODE2".GENERAL.SM.PR_MODE_2_ON;
      U     "DB_POWER_SAVING_MODE2".MODE.PR_ASU_HEATING;
      O     ;
      U     "DB_POWER_SAVING_MODE2".GENERAL.SM.PR_MODE_2_ON;
      UN    "DB_POWER_SAVING_MODE2".MODE.PR_ASU_HEATING;
      )     ;
      O     ;
      UN    "DB_POWER_SAVING_MODE2".GENERAL.SM.PR_MODE_2_ON;
      U(    ;
      ON    "ASU_LOOP_C_ON";
      O     "81CLT81_t>t_SP";
      )     ;
      O     ;
      U     "PR_STOP_PROD_FANS";
      U     "DB_GRP_81".PP61.SM.MotorOff;
      )     ;
      U(    ;
      O     "LOG_0";
      O     "LOG_1";
      )     ;
      ON    "DB_PROG".PRIMER.SM.ASU_REGULATION_ON;
      O     "DB_DIGIT".FM.G81_MT33;
      O     "DB_DIGIT".FM.G81_MT53;
      O     "DB_DIGIT".FM.G81_FAN71;
      O     "DB_DIGIT".FM.G81_FAN72;
      ON    "FDB_DIGIT".R27_81DOO08_OK;
      O     "DB_GRP_80".FAN01.SM.GeneralError;
      O     "DB_GRP_80".FAN58.SM.GeneralError;
      O     "DB_GRP_80".FAN61.SM.GeneralError;
      O     "DB_GRP_80".FAN62.SM.GeneralError;
      O     "DB_GRP_80".FAN91.SM.GeneralError;
      O     "DB_GRP_81".FAN71.SM.GeneralError;
      O     "DB_GRP_81".FAN72.SM.GeneralError;
      O     ;
      UN    "DB_PROG".PRIMER.SM.ON;
      UN    "DB_PROG".PRIMER.SM.STOP;
      )     ;
      UN    "DB_Gest_ES".FLAG._080;
      =     #AutoOn;
      U     L     20.0;
      U     "DB_PROG".PRIMER.SM.ASU_REGULATION_ON;
      U(    ;
      UN    "DB_POWER_SAVING_MODE2".GENERAL.SM.PR_MODE_2_ON;
      U(    ;
      O     "ASU_LOOP_C_ON";
      ON    "81CLT81_t>t_SP";
      )     ;
      O     ;
      U     "LOG_1";
      U     "LOG_0";
      O     ;
      U     "DB_POWER_SAVING_MODE2".GENERAL.SM.PR_MODE_2_ON;
      U     "DB_POWER_SAVING_MODE2".MODE.PR_ASU_HEATING;
      )     ;
      UN    #AutoOn;
      =     #AutoOff;
NETWORK
TITLE =FIRE ALARM CLOSE

      UN    "FDB_DIGIT".M0_FIRE_ALARM_OK;
      =     "DB_GRP_81".VA51.CW.ForceClose;
NETWORK
TITLE ==81VA51-M1 CONTROL HEATING VALVE

      U     #RelControl;
      =     L     20.0;
      BLD   103;
      U     #RelError;
      =     L     20.1;
      BLD   103;
      U     #AutoOn;
      =     L     20.2;
      BLD   103;
      U     #AutoOff;
      =     L     20.3;
      BLD   103;
      U     "R27-0AC31+27H2-F4:14";
      =     L     20.4;
      BLD   103;
      U     "R27-81VA51+X-M1:4";
      =     L     20.5;
      BLD   103;
      U     "R27-81VA51+X-M1:4'";
      =     L     20.6;
      BLD   103;
      U     #ErrorConfirm;
      =     L     20.7;
      BLD   103;
      CALL "FC_FLAP" (
           REL_CONTROL              := L     20.0,
           REL_ERROR                := L     20.1,
           CL                       := #CL,
           CR                       := #CR,
           AUTO_OPEN                := L     20.2,
           AUTO_CLOSE               := L     20.3,
           FUSE                     := L     20.4,
           LS_OPEN                  := L     20.5,
           LS_CLOSE                 := L     20.6,
           ERROR_CONFIRM            := L     20.7,
           MAX_RUNTIME              := 75,
           OPEN                     := "R27-81VA51+27H3-K1.3:A1",
           CLOSE                    := "R27-81VA51+27H3-K1.2:A1",
           DDB                      := "DB_GRP_81".VA51);
      NOP   0;
NETWORK
TITLE ==81VA51-M1 CONTROL HEATING VALVE POSITION

      CALL "FC_ANALOG_IN2" (
           INPUT                    := "R27-81VA51+X-M1:1.31",
           I_MIN                    := 2.096000e+003,
           I_MAX                    := 9.115000e+003,
           O_MIN                    := 0.000000e+000,
           O_MAX                    := 1.000000e+002,
           VALUE                    := "DB_GRP_81".VA51.PV.Position);
      NOP   0;
NETWORK
TITLE ==81MT53-A41 EXCESS TEMPERATURE PREHEATER

      U     #ErrorConfirm;
      =     "R27-81MT53+27H3-K41:A1";
      U     "R27-81MT53+27H3-K41:A1";
      R     "DB_DIGIT".FM.G81_MT53;
      U     "FDB_DIGIT".R27_MT53_TEMP_OK;
      =     "DB_DIGIT".SM.G81_MT53;
      U     "DB_DIGIT".SM.G81_MT53;
      NOT   ;
      U     #RelErrorCL;
      U     #RelErrorCR;
      S     "DB_DIGIT".FM.G81_MT53;
      NOP   0;
NETWORK
TITLE ==81FIL63-B22.1 DRY RUN PROTECTION

      U     #ErrorConfirm;
      R     "DB_DIGIT".FM.G81_FIL63_B22_1;
      U     "R27-81FIL63+X-B22.1:4";
      =     "DB_DIGIT".SM.G81_FIL63_B22_1;
      U     "DB_DIGIT".SM.G81_FIL63_B22_1;
      NOT   ;
      U     #RelErrorCL;
      U     #RelErrorCR;
      S     "DB_DIGIT".FM.G81_FIL63_B22_1;
      NOP   0;
NETWORK
TITLE ==81FIL63-B22 MIN LEVEL

      U     #ErrorConfirm;
      R     "DB_DIGIT".FM.G81_FIL63_B22;
      U(    ;
      O     "R27-81FIL63+X-B22:4";
      ON    "R27-81FIL63+X-B22:4";
      )     ;
      =     "DB_DIGIT".SM.G81_FIL63_B22;
      U     "DB_DIGIT".SM.G81_FIL63_B22;
      NOT   ;
      U     #RelErrorCL;
      U     #RelErrorCR;
      S     "DB_DIGIT".FM.G81_FIL63_B22;
      NOP   0;
NETWORK
TITLE ==81FIL63-B21 MAX LEVEL

      U     #ErrorConfirm;
      R     "DB_DIGIT".FM.G81_FIL63_B21;
      U     "R27-81FIL63+X-B21:4";
      =     "DB_DIGIT".SM.G81_FIL63_B21;
      U     "DB_DIGIT".SM.G81_FIL63_B21;
      NOT   ;
      U     #RelErrorCL;
      U     #RelErrorCR;
      S     "DB_DIGIT".FM.G81_FIL63_B21;
      NOP   0;
NETWORK
TITLE =81FIL63 LEVEL SENSOR PLAUSIBILITY FAULT

      U     #ErrorConfirm;
      R     "DB_DIGIT".FM.G81_FIL63_PLAUS;
      U(    ;
      U     "DB_DIGIT".FM.G81_FIL63_B22_1;
      UN    "DB_DIGIT".FM.G81_FIL63_B22;
      O     ;
      U(    ;
      ON    "DB_DIGIT".SM.G81_FIL63_B22_1;
      ON    "DB_DIGIT".SM.G81_FIL63_B22;
      )     ;
      UN    "DB_DIGIT".SM.G81_FIL63_B21;
      )     ;
      U     #RelErrorCL;
      U     #RelErrorCR;
      S     "DB_DIGIT".FM.G81_FIL63_PLAUS;
      NOP   0;
NETWORK
TITLE ==81PP61-U1 CONTROL/ERROR RELEASE

      U     "LOG_1";
      =     L     20.0;
      U     L     20.0;
      U     #RelControlCL;
      U     #RelControlCR;
      UN    "DB_DIGIT".FM.G81_FIL63_B22_1;
      U(    ;
      ON    "DB_DIGIT".FM.G81_FIL63_PLAUS;
      O     "DB_DIGIT".FM.G81_FIL63_PLAUS;
      )     ;
      UN    "DB_DIGIT".FM.G81_MT34_1_L2;
      UN    "DB_DIGIT".FM.G81_MT34_A41_L2;
      =     #RelControl;
      U     L     20.0;
      U     #RelErrorCL;
      U     #RelErrorCR;
      =     #RelError;
NETWORK
TITLE =RESET USING ESTOP ON THE CABINET

      U     "DB_CABINET_R27".FM.ESTOP;
      =     "DB_GRP_81".PP61.CW.ESTOP_Res;
NETWORK
TITLE ==81PP61-U1 HUMIDITY TIMER

      U     "DB_PROG".PRIMER.SM.ASU_REGULATION_ON;
      U     "ASU_LOOP_B_ON";
      U     "81CLM82_r.H>r.H_SP";
      U(    ;
      L     "DB_GRP_81".PP61.PV.Frq_AV;
      L     7.300000e+000;
      <R    ;
      )     ;
      L     S5T#3M;
      SE    "T_81PP61_STOP_DELAY";
      U(    ;
      ON    "81CLM82_r.H>r.H_SP";
      ON    "ASU_LOOP_B_ON";
      ON    "DB_PROG".PRIMER.SM.ASU_REGULATION_ON;
      )     ;
      R     "T_81PP61_STOP_DELAY";
      NOP   0;
      NOP   0;
      NOP   0;
NETWORK
TITLE ==81PP61-U1 HUMIDIFIER PID SETPOINT TRANSFER

      U     "DB_GRP_81".PP61.SM.AutomaticMode;
      =     L     20.0;
      U     L     20.0;
      UN    "M750.4";
      SPBNB _009;
      L     "DB_GRP_81".PID_HUM.PV.ManipulatedVariable_AV;
      T     "DB_GRP_81".PP61.PV.Frq_SP;
_009: NOP   0;
      U     L     20.0;
      U     "M750.4";
      U     "LOG_0";
      SPBNB _00a;
      L     2.200000e+001;
      T     "DB_GRP_81".PP61.PV.Frq_SP;
_00a: NOP   0;
NETWORK
TITLE =

      U     "LOG_1";
      U(    ;
      L     "DB_GRP_81".CLM82_HUM.PV.AV;
      L     "DB_GRP_81".CLM82_HUM.PV.SP_AV;
      <R    ;
      )     ;
      =     L     20.0;
      U     L     20.0;
      L     S5T#20S;
      SE    T    210;
      NOP   0;
      NOP   0;
      NOP   0;
      U     T    210;
      =     "M750.0";
      U     L     20.0;
      U(    ;
      L     "DB_GRP_81".CLM82_HUM.PV.AV;
      L     "DB_GRP_81".CLM82_HUM.PV.Limit_02;
      >=R   ;
      )     ;
      L     S5T#20S;
      SE    T    214;
      NOP   0;
      NOP   0;
      NOP   0;
      U     T    214;
      =     "M750.4";
NETWORK
TITLE ==81PP61-U1 HUMIDIFIER PUMP CONTROL SIGNALS

      U     "DB_CABINET_R27".SM.CtrlRelease_A;
      =     L     20.0;
      U     L     20.0;
      U     "DB_PROG".PRIMER.SM.ASU_REGULATION_ON;
      U(    ;
      UN    "DB_POWER_SAVING_MODE2".GENERAL.SM.PR_MODE_2_ON;
      U(    ;
      O     "ASU_LOOP_B_ON";
      O     "M750.0";
      )     ;
      UN    "81CLM82_r.H>r.H_SP";
      O     ;
      U     "DB_POWER_SAVING_MODE2".GENERAL.SM.PR_MODE_2_ON;
      U     "DB_POWER_SAVING_MODE2".MODE.PR_ASU_HUMIDIFYING;
      )     ;
      UN    "DB_DIGIT".FM.G81_FIL63_B22;
      =     #AutoOn;
      U     L     20.0;
      U(    ;
      UN    "DB_POWER_SAVING_MODE2".GENERAL.SM.PR_MODE_2_ON;
      U(    ;
      O     "T_81PP61_STOP_DELAY";
      O     M   1000.1;
      O     ;
      UN    "ASU_LOOP_B_ON";
      U(    ;
      L     "DB_GRP_81".CLM82_HUM.PV.AV;
      L     "DB_GRP_81".CLM82_HUM.PV.SP_AV;
      >=R   ;
      )     ;
      )     ;
      O     ;
      U     "DB_POWER_SAVING_MODE2".GENERAL.SM.PR_MODE_2_ON;
      UN    "DB_POWER_SAVING_MODE2".MODE.PR_ASU_HUMIDIFYING;
      ON    "DB_PROG".PRIMER.SM.ASU_REGULATION_ON;
      O     "DB_DIGIT".FM.G81_FAN71;
      O     "DB_DIGIT".FM.G81_FAN72;
      O     "DB_GRP_80".FAN01.SM.GeneralError;
      O     "DB_GRP_80".FAN58.SM.GeneralError;
      O     "DB_GRP_80".FAN61.SM.GeneralError;
      O     "DB_GRP_80".FAN62.SM.GeneralError;
      O     "DB_GRP_80".FAN91.SM.GeneralError;
      O     "DB_GRP_81".FAN71.SM.GeneralError;
      O     "DB_GRP_81".FAN72.SM.GeneralError;
      )     ;
      =     #AutoOff;
NETWORK
TITLE ==81PP61-U1 HUMIDIFIER PUMP

      U     #RelControl;
      =     L     20.0;
      BLD   103;
      U     #RelError;
      =     L     20.1;
      BLD   103;
      U     #AutoOn;
      =     L     20.2;
      BLD   103;
      U     #AutoOff;
      =     L     20.3;
      BLD   103;
      U     "R27-81PP61+27H3-Q1:14";
      =     L     20.4;
      BLD   103;
      U     "LOG_1";
      =     L     20.5;
      BLD   103;
      U     #ErrorConfirm;
      =     L     20.6;
      BLD   103;
      U     "LOG_0";
      =     L     20.7;
      BLD   103;
      U     "LOG_0";
      =     L     21.0;
      BLD   103;
      U     "LOG_0";
      =     L     21.1;
      BLD   103;
      CALL "FC_MOTOR_FC" (
           REL_CONTROL              := L     20.0,
           REL_ERROR                := L     20.1,
           CL                       := #CL,
           CR                       := #CR,
           AUTO_START               := L     20.2,
           AUTO_STOP                := L     20.3,
           MPS                      := L     20.4,
           PTC_WAR                  := L     20.5,
           ERROR_CONFIRM            := L     20.6,
           FC_STATUS                := "R27-81PP61-27H3-STAT",
           FC_DI                    := "R27-81PP61-27H3-DI",
           FC_FREQ_AV               := "R27-81PP61-27H3-FRQAV",
           MAX_TIME_RAMP            := 30,
           SW_ENABLE                := L     20.7,
           SW_START                 := L     21.0,
           SW_STOP                  := L     21.1,
           FC_CTRL                  := "R27-81PP61-27H3-CTRL",
           FC_FREQ_SP               := "R27-81PP61-27H3-FRQSP",
           LAMP_ON                  := #LAMP_ON,
           DELAY_ON                 := "DELAY_ON",
           DDB                      := "DB_GRP_81".PP61);
      NOP   0;
NETWORK
TITLE ==81PP61-B85 VIBRATION MONITORING

      U     #RelError;
      =     L     20.0;
      BLD   103;
      U     "DB_GRP_81".PP61.SM.MotorOn;
      =     L     20.1;
      BLD   103;
      UN    "R27-81PP61+27H3-A85:25";
      =     L     20.2;
      BLD   103;
      UN    "R27-81PP61+27H3-A85:27";
      =     L     20.3;
      BLD   103;
      U     #ErrorConfirm;
      =     L     20.4;
      BLD   103;
      CALL "FC_MOTOR_VIBRATION" (
           REL_ERROR                := L     20.0,
           MOTOR_ON                 := L     20.1,
           PRE_ALARM                := L     20.2,
           ALARM                    := L     20.3,
           ERROR_CONFIRM            := L     20.4,
           DDB                      := "DB_VIBRATION_SENSORS".V_81PP61_A85);
      NOP   0;
NETWORK
TITLE ==81CLV63-B25 FLOW RATE MONITORING

      U     "LOG_1";
      =     L     20.0;
      U     L     20.0;
      U     "LOG_0";
      U     "DB_CABINET_R21".CTRL.ResetFault;
      FP    "81CLV63_SET_PE";
      SPBNB _00b;
      L     2.117200e+003;
      T     "DB_ANALOG_MEDIA".G81_CLV63;
_00b: NOP   0;
      U     L     20.0;
      U     "R27-81CLV63+X-B25:Imp";
      FP    "81CLV63_IMP_PE";
      SPBNB _00c;
      L     "DB_ANALOG_MEDIA".G81_CLV63;
      L     1.000000e-003;
      +R    ;
      T     "DB_ANALOG_MEDIA".G81_CLV63;
_00c: NOP   0;
NETWORK
TITLE ==81CLV63-B25 PILOT CONTACT FAULT

      U     #ErrorConfirm;
      R     "DB_DIGIT".FM.G81_CLV63_PILOTCONT;
      U     "R27-81CLV63+X-XS1:5";
      =     "DB_DIGIT".SM.G81_CLV63_PILOTCONT;
      U     "DB_DIGIT".SM.G81_CLV63_PILOTCONT;
      NOT   ;
      U     #RelError;
      S     "DB_DIGIT".FM.G81_CLV63_PILOTCONT;
      NOP   0;
NETWORK
TITLE ==81FIL63-Y1 CONTROL/ERROR RELEASE

      U     "LOG_1";
      =     L     20.0;
      U     L     20.0;
      U     #RelControlCL;
      U     #RelControlCR;
      UN    "DB_DIGIT".FM.G81_FIL63_B21;
      =     #RelControl;
      U     L     20.0;
      U     #RelErrorCL;
      U     #RelErrorCR;
      =     #RelError;
NETWORK
TITLE ==81FIL63-Y1 HUMIDIFER SOLENOID VALVE CONTROL SIGNALS

      U     "DB_CABINET_R27".SM.CtrlRelease_A;
      =     L     20.0;
      U     L     20.0;
      U(    ;
      O     "OPEN_ASU_FLAPS";
      O     ;
      UN    "DB_DIGIT".FM.G81_FIL63_B21;
      U     "DB_PROG".PRIMER.SM.ASU_REGULATION_ON;
      )     ;
      U     "DB_PROG".PRIMER.SM.ON;
      =     #AutoOn;
      U     L     20.0;
      UN    "DB_PROG".PRIMER.SM.ON;
      U     "T_FOLLOWUP_PURGING";
      =     #AutoOff;
NETWORK
TITLE ==81FIL63-Y1 HUMIDIFIER SOLENOID VALVE

      U     #RelControl;
      =     L     20.0;
      BLD   103;
      U     #AutoOn;
      =     L     20.1;
      BLD   103;
      U     #AutoOff;
      =     L     20.2;
      BLD   103;
      CALL "FC_VALVE" (
           REL_CONTROL              := L     20.0,
           CL                       := #CL,
           CR                       := #CR,
           AUTO_OPEN                := L     20.1,
           AUTO_CLOSE               := L     20.2,
           OPEN                     := "R27-81FIL63+X-Y1",
           DDB                      := "DB_GRP_81".FIL63_Y1);
      NOP   0;
NETWORK
TITLE ==81FTR80-B33 FILTER PRESSURE MONITORING

      U     #RelError;
      =     L     20.0;
      BLD   103;
      U     "R27-81FTR80+X-B33-XS2:4";
      =     L     20.1;
      BLD   103;
      U(    ;
      O     "DB_GRP_81".FAN71.SM.MotorOn;
      O     "DB_GRP_81".FAN72.SM.MotorOn;
      )     ;
      =     L     20.2;
      BLD   103;
      U     #ErrorConfirm;
      =     L     20.3;
      BLD   103;
      CALL "FC_ANALOG_DIGIT_MOTOR" (
           REL_ERROR                := L     20.0,
           INPUT_ANALOG             := "R27-81FTR80+X-B33-XS1:4",
           INPUT_BINARY             := L     20.1,
           I_MAX                    := 2.764800e+004,
           O_MIN                    := 0.000000e+000,
           O_MAX                    := 6.000000e+002,
           MOTOR_ON                 := L     20.2,
           MOTOR_DELAY              := 3.000000e+001,
           MAX_TIME                 := 30,
           ERROR_CONFIRM            := L     20.3,
           DDB                      := "DB_GRP_81".FTR80);
      NOP   0;
NETWORK
TITLE =FORCE 81CLT81-B40N ERR. REL. IF WINDOW IS NOT REACHED AFTER TIME

      U     #RelErrorCL;
      U     #RelErrorCR;
      U     "DB_PROG".PRIMER.SM.ASU_REGULATION_ON;
      U(    ;
      U     "DB_PROG".PRIMER.SM.ON;
      U     "T_PREPURGING_TIME";
      O     ;
      UN    "DB_PROG".PRIMER.SM.ON;
      U     "DB_PROG".PRIMER.SM.STOP;
      UN    "DB_DE".IN.PR_BOOTH_NO_CAR_INSIDE;
      )     ;
      U     "T_81CLT81_ERR_REL_DEL";
      L     S5T#10M;
      SE    "T_81CLT81_REL_ERR_FORCE";
      NOP   0;
      NOP   0;
      NOP   0;
      NOP   0;
NETWORK
TITLE ==81CLT81-B40N SETPOINT CHANGED

      U(    ;
      L     "DB_GRP_81".CLT81.PV.SP_AV;
      L     "DB_SETPOINTS".TEMP_81CLT81_SP_PREV;
      ==R   ;
      )     ;
      L     S5T#1M;
      SE    "T_81CLT81_ERR_REL_DEL";
      U(    ;
      L     "DB_GRP_81".CLT81.PV.SP_AV;
      L     "DB_SETPOINTS".TEMP_81CLT81_SP_PREV;
      <>R   ;
      )     ;
      R     "T_81CLT81_ERR_REL_DEL";
      NOP   0;
      NOP   0;
      NOP   0;
NETWORK
TITLE ==81CLT81-B40N TEMPERATURE MONITORING

      U     #RelErrorCL;
      U     #RelErrorCR;
      U     "DB_PROG".PRIMER.SM.ASU_REGULATION_ON;
      U(    ;
      U     "DB_PROG".PRIMER.SM.ON;
      U     "T_PREPURGING_TIME";
      O     ;
      UN    "DB_PROG".PRIMER.SM.ON;
      U     "DB_PROG".PRIMER.SM.STOP;
      UN    "DB_DE".IN.PR_BOOTH_NO_CAR_INSIDE;
      )     ;
      U     "T_81CLT81_ERR_REL_DEL";
      U(    ;
      O(    ;
      L     "DB_GRP_81".CLT81.PV.AV;
      L     "DB_GRP_81".CLT81.PV.Limit_01;
      >R    ;
      )     ;
      O     "T_81CLT81_REL_ERR_FORCE";
      O     "81CTL81_REL_ERROR";
      )     ;
      =     "81CTL81_REL_ERROR";
      U     "81CTL81_REL_ERROR";
      =     L     20.0;
      BLD   103;
      U     #ErrorConfirm;
      =     L     20.1;
      BLD   103;
      CALL "FC_TEMP_HEATER2" (
           REL_ERROR                := L     20.0,
           ERROR_CONFIRM            := L     20.1,
           INPUT                    := "R27-81CLT81+X-B40N:-",
           I_MAX                    := 2.654800e+004,
           O_MIN                    := -3.000000e+001,
           O_MAX                    := 6.000000e+001,
           SETPOINT                 := "DB_GRP_81".CLT81.PV.SP_AV,
           MAX_TIME                 := 30,
           WAR_LIMIT                := 2.000000e+000,
           ERR_LIMIT                := 4.000000e+000,
           DDB                      := "DB_GRP_81".CLT81);
      NOP   0;
NETWORK
TITLE =CURRENT SETPOINT TO PREVIOUS SETPOINT

      L     "DB_GRP_81".CLT81.PV.SP_AV;
      T     "DB_SETPOINTS".TEMP_81CLT81_SP_PREV;
      NOP   0;
NETWORK
TITLE ==81CLTM10-B49N OUTSIDE HUMIDITY MONITORING

      U     "LOG_0";
      =     L     20.0;
      BLD   103;
      U     #ErrorConfirm;
      =     L     20.1;
      BLD   103;
      CALL "FC_TEMP_HEATER2" (
           REL_ERROR                := L     20.0,
           ERROR_CONFIRM            := L     20.1,
           INPUT                    := "R27-81CLM10+X-B49N:2",
           I_MAX                    := 2.764800e+004,
           O_MIN                    := 0.000000e+000,
           O_MAX                    := 1.000000e+002,
           SETPOINT                 := 0.000000e+000,
           MAX_TIME                 := 0,
           WAR_LIMIT                := 0.000000e+000,
           ERR_LIMIT                := 0.000000e+000,
           DDB                      := "DB_GRP_81".CLM10_HUM);
      NOP   0;
NETWORK
TITLE ==81CLM10 HUMIDITY SENSOR FAULT


      U(    ;
      L     "R27-81CLM10+X-B49N:2";
      L     L#32768;
      <>I   ;
      )     ;
      U(    ;
      L     "R27-81CLM10+X-B49N:2";
      L     -32768;
      <>I   ;
      )     ;
      =     #OUT_HUM_SENSOR_OK;

      U     #ErrorConfirm;
      R     "DB_DIGIT".FM.G81_81CLM10_HUM;
      U     #RelErrorCL;
      U     #RelErrorCR;
      UN    #OUT_HUM_SENSOR_OK;
      S     "DB_DIGIT".FM.G81_81CLM10_HUM;

NETWORK
TITLE ==81CLM10-B49N OUTSIDE TEMPERATURE MONITORING

      U     "LOG_0";
      =     L     20.0;
      BLD   103;
      U     #ErrorConfirm;
      =     L     20.1;
      BLD   103;
      CALL "FC_TEMP_HEATER2" (
           REL_ERROR                := L     20.0,
           ERROR_CONFIRM            := L     20.1,
           INPUT                    := "R27-81CLM10+X-B49N:5",
           I_MAX                    := 2.764800e+004,
           O_MIN                    := -2.000000e+001,
           O_MAX                    := 8.000000e+001,
           SETPOINT                 := 0.000000e+000,
           MAX_TIME                 := 0,
           WAR_LIMIT                := 0.000000e+000,
           ERR_LIMIT                := 0.000000e+000,
           DDB                      := "DB_GRP_81".CLM10_TEMP);
      NOP   0;
NETWORK
TITLE ==81CLM10 TEMPERATURE SENSOR FAULT

      U(    ;
      L     "R27-81CLM10+X-B49N:5";
      L     L#32768;
      <>I   ;
      )     ;
      U(    ;
      L     "R27-81CLM10+X-B49N:5";
      L     -32768;
      <>I   ;
      )     ;
      =     #OUT_TEMP_SENSOR_OK;

      U     #ErrorConfirm;
      R     "DB_DIGIT".FM.G81_81CLM10_TEMP;
      U     #RelErrorCL;
      U     #RelErrorCR;
      UN    #OUT_TEMP_SENSOR_OK;
      S     "DB_DIGIT".FM.G81_81CLM10_TEMP;




NETWORK
TITLE =FORCE 81CLM82-B49N ERR. REL. IF WINDOW IS NOT REACHED AFTER TIME

      U     #RelErrorCL;
      U     #RelErrorCR;
      U     "DB_PROG".PRIMER.SM.ASU_REGULATION_ON;
      U(    ;
      U     "DB_PROG".PRIMER.SM.ON;
      U     "T_PREPURGING_TIME";
      O     ;
      UN    "DB_PROG".PRIMER.SM.ON;
      U     "DB_PROG".PRIMER.SM.STOP;
      UN    "DB_DE".IN.PR_BOOTH_NO_CAR_INSIDE;
      )     ;
      U     "T_81CLM82_ERR_REL_DEL";
      L     S5T#10M;
      SE    "T_81CLM82_REL_ERR_FORCE";
      NOP   0;
      NOP   0;
      NOP   0;
      NOP   0;
NETWORK
TITLE ==81CLM82-B49N SETPOINT CHANGED

      U(    ;
      L     "DB_GRP_81".CLM82_HUM.PV.SP_AV;
      L     "DB_SETPOINTS".HUM_81CLM82_SP_PREV;
      ==R   ;
      )     ;
      L     S5T#1M;
      SE    "T_81CLM82_ERR_REL_DEL";
      U(    ;
      L     "DB_GRP_81".CLM82_HUM.PV.SP_AV;
      L     "DB_SETPOINTS".HUM_81CLM82_SP_PREV;
      <>R   ;
      )     ;
      R     "T_81CLM82_ERR_REL_DEL";
      NOP   0;
      NOP   0;
      NOP   0;
NETWORK
TITLE ==81CLTM82-B49N HUMIDITY MONITORING

      U     #RelErrorCL;
      U     #RelErrorCR;
      U     "DB_PROG".PRIMER.SM.ASU_REGULATION_ON;
      U(    ;
      U     "DB_PROG".PRIMER.SM.ON;
      U     "T_PREPURGING_TIME";
      O     ;
      UN    "DB_PROG".PRIMER.SM.ON;
      U     "DB_PROG".PRIMER.SM.STOP;
      UN    "DB_DE".IN.PR_BOOTH_NO_CAR_INSIDE;
      )     ;
      U     "T_81CLM82_ERR_REL_DEL";
      U(    ;
      U(    ;
      L     "DB_GRP_81".CLM82_HUM.PV.AV;
      L     "DB_GRP_81".CLM82_HUM.PV.Limit_01;
      >R    ;
      )     ;
      U(    ;
      L     "DB_GRP_81".CLM82_HUM.PV.AV;
      L     "DB_GRP_81".CLM82_HUM.PV.Limit_04;
      <R    ;
      )     ;
      O     "T_81CLM82_REL_ERR_FORCE";
      O     "81CLM82_HUM_REL_ERROR";
      )     ;
      =     "81CLM82_HUM_REL_ERROR";
      U     "81CLM82_HUM_REL_ERROR";
      =     L     20.0;
      BLD   103;
      U     #ErrorConfirm;
      =     L     20.1;
      BLD   103;
      CALL "FC_TEMP_HEATER2" (
           REL_ERROR                := L     20.0,
           ERROR_CONFIRM            := L     20.1,
           INPUT                    := "R27-81CLM82+X-B49N:2",
           I_MAX                    := 3.000100e+004,
           O_MIN                    := 0.000000e+000,
           O_MAX                    := 1.000000e+002,
           SETPOINT                 := "DB_GRP_81".CLM82_HUM.PV.SP_AV,
           MAX_TIME                 := 30,
           WAR_LIMIT                := 5.000000e+000,
           ERR_LIMIT                := 1.000000e+001,
           DDB                      := "DB_GRP_81".CLM82_HUM);
      NOP   0;
NETWORK
TITLE =AUTORESET UMID/TEMP ASU

      U     "LOG_1";
      U(    ;
      L     "DB_GRP_81".CLM82_HUM.PV.AV;
      L     "DB_GRP_81".CLM82_HUM.PV.Limit_01;
      >R    ;
      )     ;
      U(    ;
      L     "DB_GRP_81".CLM82_HUM.PV.AV;
      L     "DB_GRP_81".CLM82_HUM.PV.Limit_04;
      <R    ;
      )     ;
      U(    ;
      L     "DB_GRP_81".CLT81.PV.AV;
      L     "DB_GRP_81".CLT81.PV.Limit_01;
      >R    ;
      )     ;
      L     S5T#2S;
      SI    T     65;
      NOP   0;
      NOP   0;
      NOP   0;
      U     T     65;
      =     "Auto_reset_R27";
NETWORK
TITLE =CURRENT SETPOINT TO PREVIOUS SETPOINT

      L     "DB_GRP_81".CLM82_HUM.PV.SP_AV;
      T     "DB_SETPOINTS".HUM_81CLM82_SP_PREV;
      NOP   0;
NETWORK
TITLE ==81CLM82-B49N TEMPERATURE MINITORING
//IN PAP THERE IS INFORMATION THAT THIS TEMPERATURE SENSOR IS NOT USED (THERE IS
//ONE DEVICE MEASURING HUMIDITY AND TEMPERATURE)
      U     #RelErrorCL;
      U     #RelErrorCR;
      U     "DB_PROG".PRIMER.SM.ASU_REGULATION_ON;
      U(    ;
      U     "DB_PROG".PRIMER.SM.ON;
      U     "T_PREPURGING_TIME";
      O     ;
      UN    "DB_PROG".PRIMER.SM.ON;
      U     "DB_PROG".PRIMER.SM.STOP;
      UN    "DB_DE".IN.PR_BOOTH_NO_CAR_INSIDE;
      )     ;
      U(    ;
      O(    ;
      L     "DB_GRP_81".CLM82_TEMP.PV.AV;
      L     "DB_GRP_81".CLM82_TEMP.PV.Limit_01;
      >R    ;
      )     ;
      O     "81CLM82_TEMP_REL_ERROR";
      )     ;
      =     "81CLM82_TEMP_REL_ERROR";
      U     "81CLM82_TEMP_REL_ERROR";
      U     "LOG_0";
      =     L     20.0;
      BLD   103;
      U     #ErrorConfirm;
      =     L     20.1;
      BLD   103;
      CALL "FC_TEMP_HEATER2" (
           REL_ERROR                := L     20.0,
           ERROR_CONFIRM            := L     20.1,
           INPUT                    := "R27-81CLM82+X-B49N:5",
           I_MAX                    := 2.764800e+004,
           O_MIN                    := -2.000000e+001,
           O_MAX                    := 8.000000e+001,
           SETPOINT                 := "DB_GRP_81".CLM82_TEMP.PV.SP_AV,
           MAX_TIME                 := 30,
           WAR_LIMIT                := 1.500000e+000,
           ERR_LIMIT                := 3.000000e+000,
           DDB                      := "DB_GRP_81".CLM82_TEMP);
      NOP   0;
NETWORK
TITLE =END



END_FUNCTION

